VERSION 5.7 ;
  NOWIREEXTENSIONATPIN ON ;
  DIVIDERCHAR "/" ;
  BUSBITCHARS "[]" ;
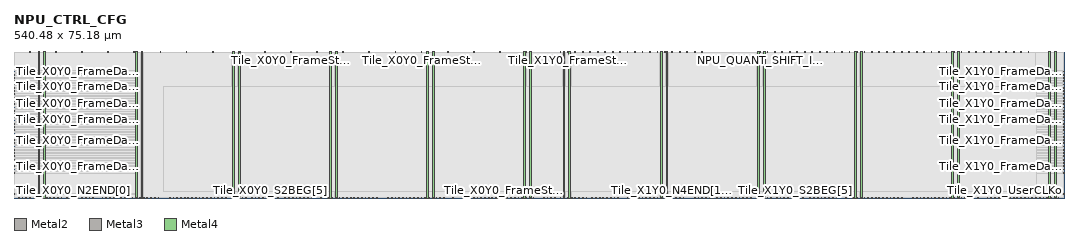
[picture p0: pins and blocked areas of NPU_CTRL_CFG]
MACRO NPU_CTRL_CFG
  CLASS BLOCK ;
  FOREIGN NPU_CTRL_CFG ;
  ORIGIN 0.000 0.000 ;
  SIZE 540.480 BY 75.180 ;
  PIN NPU_ARRAY_EN
    DIRECTION OUTPUT ;
    USE SIGNAL ;
    ANTENNADIFFAREA 2.647800 ;
    PORT
      LAYER Metal2 ;
        RECT 502.840 74.780 503.240 75.180 ;
    END
  END NPU_ARRAY_EN
  PIN NPU_COMPUTE_BANK_SWAP
    DIRECTION OUTPUT ;
    USE SIGNAL ;
    ANTENNADIFFAREA 2.647800 ;
    PORT
      LAYER Metal2 ;
        RECT 522.040 74.780 522.440 75.180 ;
    END
  END NPU_COMPUTE_BANK_SWAP
  PIN NPU_PSUM_LUT_EN
    DIRECTION OUTPUT ;
    USE SIGNAL ;
    ANTENNADIFFAREA 2.647800 ;
    PORT
      LAYER Metal2 ;
        RECT 510.520 74.780 510.920 75.180 ;
    END
  END NPU_PSUM_LUT_EN
  PIN NPU_PSUM_SKEW_EN
    DIRECTION OUTPUT ;
    USE SIGNAL ;
    ANTENNADIFFAREA 2.647800 ;
    PORT
      LAYER Metal2 ;
        RECT 518.200 74.780 518.600 75.180 ;
    END
  END NPU_PSUM_SKEW_EN
  PIN NPU_PSUM_SYSTOLIC_EN
    DIRECTION OUTPUT ;
    USE SIGNAL ;
    ANTENNADIFFAREA 2.647800 ;
    PORT
      LAYER Metal2 ;
        RECT 506.680 74.780 507.080 75.180 ;
    END
  END NPU_PSUM_SYSTOLIC_EN
  PIN NPU_QUANT_SHIFT_EN
    DIRECTION OUTPUT ;
    USE SIGNAL ;
    ANTENNADIFFAREA 2.647800 ;
    PORT
      LAYER Metal2 ;
        RECT 499.000 74.780 499.400 75.180 ;
    END
  END NPU_QUANT_SHIFT_EN
  PIN NPU_QUANT_SHIFT_IN0
    DIRECTION OUTPUT ;
    USE SIGNAL ;
    ANTENNADIFFAREA 2.647800 ;
    PORT
      LAYER Metal2 ;
        RECT 383.800 74.780 384.200 75.180 ;
    END
  END NPU_QUANT_SHIFT_IN0
  PIN NPU_QUANT_SHIFT_IN1
    DIRECTION OUTPUT ;
    USE SIGNAL ;
    ANTENNADIFFAREA 2.647800 ;
    PORT
      LAYER Metal2 ;
        RECT 387.640 74.780 388.040 75.180 ;
    END
  END NPU_QUANT_SHIFT_IN1
  PIN NPU_QUANT_SHIFT_IN10
    DIRECTION OUTPUT ;
    USE SIGNAL ;
    ANTENNADIFFAREA 2.647800 ;
    PORT
      LAYER Metal2 ;
        RECT 422.200 74.780 422.600 75.180 ;
    END
  END NPU_QUANT_SHIFT_IN10
  PIN NPU_QUANT_SHIFT_IN11
    DIRECTION OUTPUT ;
    USE SIGNAL ;
    ANTENNADIFFAREA 2.647800 ;
    PORT
      LAYER Metal2 ;
        RECT 426.040 74.780 426.440 75.180 ;
    END
  END NPU_QUANT_SHIFT_IN11
  PIN NPU_QUANT_SHIFT_IN12
    DIRECTION OUTPUT ;
    USE SIGNAL ;
    ANTENNADIFFAREA 2.647800 ;
    PORT
      LAYER Metal2 ;
        RECT 429.880 74.780 430.280 75.180 ;
    END
  END NPU_QUANT_SHIFT_IN12
  PIN NPU_QUANT_SHIFT_IN13
    DIRECTION OUTPUT ;
    USE SIGNAL ;
    ANTENNADIFFAREA 2.647800 ;
    PORT
      LAYER Metal2 ;
        RECT 433.720 74.780 434.120 75.180 ;
    END
  END NPU_QUANT_SHIFT_IN13
  PIN NPU_QUANT_SHIFT_IN14
    DIRECTION OUTPUT ;
    USE SIGNAL ;
    ANTENNADIFFAREA 2.647800 ;
    PORT
      LAYER Metal2 ;
        RECT 437.560 74.780 437.960 75.180 ;
    END
  END NPU_QUANT_SHIFT_IN14
  PIN NPU_QUANT_SHIFT_IN15
    DIRECTION OUTPUT ;
    USE SIGNAL ;
    ANTENNADIFFAREA 2.647800 ;
    PORT
      LAYER Metal2 ;
        RECT 441.400 74.780 441.800 75.180 ;
    END
  END NPU_QUANT_SHIFT_IN15
  PIN NPU_QUANT_SHIFT_IN16
    DIRECTION OUTPUT ;
    USE SIGNAL ;
    ANTENNADIFFAREA 2.647800 ;
    PORT
      LAYER Metal2 ;
        RECT 445.240 74.780 445.640 75.180 ;
    END
  END NPU_QUANT_SHIFT_IN16
  PIN NPU_QUANT_SHIFT_IN17
    DIRECTION OUTPUT ;
    USE SIGNAL ;
    ANTENNADIFFAREA 2.647800 ;
    PORT
      LAYER Metal2 ;
        RECT 449.080 74.780 449.480 75.180 ;
    END
  END NPU_QUANT_SHIFT_IN17
  PIN NPU_QUANT_SHIFT_IN18
    DIRECTION OUTPUT ;
    USE SIGNAL ;
    ANTENNADIFFAREA 2.647800 ;
    PORT
      LAYER Metal2 ;
        RECT 452.920 74.780 453.320 75.180 ;
    END
  END NPU_QUANT_SHIFT_IN18
  PIN NPU_QUANT_SHIFT_IN19
    DIRECTION OUTPUT ;
    USE SIGNAL ;
    ANTENNADIFFAREA 2.647800 ;
    PORT
      LAYER Metal2 ;
        RECT 456.760 74.780 457.160 75.180 ;
    END
  END NPU_QUANT_SHIFT_IN19
  PIN NPU_QUANT_SHIFT_IN2
    DIRECTION OUTPUT ;
    USE SIGNAL ;
    ANTENNADIFFAREA 2.647800 ;
    PORT
      LAYER Metal2 ;
        RECT 391.480 74.780 391.880 75.180 ;
    END
  END NPU_QUANT_SHIFT_IN2
  PIN NPU_QUANT_SHIFT_IN20
    DIRECTION OUTPUT ;
    USE SIGNAL ;
    ANTENNADIFFAREA 2.647800 ;
    PORT
      LAYER Metal2 ;
        RECT 460.600 74.780 461.000 75.180 ;
    END
  END NPU_QUANT_SHIFT_IN20
  PIN NPU_QUANT_SHIFT_IN21
    DIRECTION OUTPUT ;
    USE SIGNAL ;
    ANTENNADIFFAREA 2.647800 ;
    PORT
      LAYER Metal2 ;
        RECT 464.440 74.780 464.840 75.180 ;
    END
  END NPU_QUANT_SHIFT_IN21
  PIN NPU_QUANT_SHIFT_IN22
    DIRECTION OUTPUT ;
    USE SIGNAL ;
    ANTENNADIFFAREA 2.647800 ;
    PORT
      LAYER Metal2 ;
        RECT 468.280 74.780 468.680 75.180 ;
    END
  END NPU_QUANT_SHIFT_IN22
  PIN NPU_QUANT_SHIFT_IN23
    DIRECTION OUTPUT ;
    USE SIGNAL ;
    ANTENNADIFFAREA 2.647800 ;
    PORT
      LAYER Metal2 ;
        RECT 472.120 74.780 472.520 75.180 ;
    END
  END NPU_QUANT_SHIFT_IN23
  PIN NPU_QUANT_SHIFT_IN24
    DIRECTION OUTPUT ;
    USE SIGNAL ;
    ANTENNADIFFAREA 2.647800 ;
    PORT
      LAYER Metal2 ;
        RECT 475.960 74.780 476.360 75.180 ;
    END
  END NPU_QUANT_SHIFT_IN24
  PIN NPU_QUANT_SHIFT_IN25
    DIRECTION OUTPUT ;
    USE SIGNAL ;
    ANTENNADIFFAREA 2.647800 ;
    PORT
      LAYER Metal2 ;
        RECT 479.800 74.780 480.200 75.180 ;
    END
  END NPU_QUANT_SHIFT_IN25
  PIN NPU_QUANT_SHIFT_IN26
    DIRECTION OUTPUT ;
    USE SIGNAL ;
    ANTENNADIFFAREA 2.647800 ;
    PORT
      LAYER Metal2 ;
        RECT 483.640 74.780 484.040 75.180 ;
    END
  END NPU_QUANT_SHIFT_IN26
  PIN NPU_QUANT_SHIFT_IN27
    DIRECTION OUTPUT ;
    USE SIGNAL ;
    ANTENNADIFFAREA 2.647800 ;
    PORT
      LAYER Metal2 ;
        RECT 487.480 74.780 487.880 75.180 ;
    END
  END NPU_QUANT_SHIFT_IN27
  PIN NPU_QUANT_SHIFT_IN28
    DIRECTION OUTPUT ;
    USE SIGNAL ;
    ANTENNADIFFAREA 2.647800 ;
    PORT
      LAYER Metal2 ;
        RECT 491.320 74.780 491.720 75.180 ;
    END
  END NPU_QUANT_SHIFT_IN28
  PIN NPU_QUANT_SHIFT_IN29
    DIRECTION OUTPUT ;
    USE SIGNAL ;
    ANTENNADIFFAREA 2.647800 ;
    PORT
      LAYER Metal2 ;
        RECT 495.160 74.780 495.560 75.180 ;
    END
  END NPU_QUANT_SHIFT_IN29
  PIN NPU_QUANT_SHIFT_IN3
    DIRECTION OUTPUT ;
    USE SIGNAL ;
    ANTENNADIFFAREA 2.647800 ;
    PORT
      LAYER Metal2 ;
        RECT 395.320 74.780 395.720 75.180 ;
    END
  END NPU_QUANT_SHIFT_IN3
  PIN NPU_QUANT_SHIFT_IN4
    DIRECTION OUTPUT ;
    USE SIGNAL ;
    ANTENNADIFFAREA 2.647800 ;
    PORT
      LAYER Metal2 ;
        RECT 399.160 74.780 399.560 75.180 ;
    END
  END NPU_QUANT_SHIFT_IN4
  PIN NPU_QUANT_SHIFT_IN5
    DIRECTION OUTPUT ;
    USE SIGNAL ;
    ANTENNADIFFAREA 2.647800 ;
    PORT
      LAYER Metal2 ;
        RECT 403.000 74.780 403.400 75.180 ;
    END
  END NPU_QUANT_SHIFT_IN5
  PIN NPU_QUANT_SHIFT_IN6
    DIRECTION OUTPUT ;
    USE SIGNAL ;
    ANTENNADIFFAREA 2.647800 ;
    PORT
      LAYER Metal2 ;
        RECT 406.840 74.780 407.240 75.180 ;
    END
  END NPU_QUANT_SHIFT_IN6
  PIN NPU_QUANT_SHIFT_IN7
    DIRECTION OUTPUT ;
    USE SIGNAL ;
    ANTENNADIFFAREA 2.647800 ;
    PORT
      LAYER Metal2 ;
        RECT 410.680 74.780 411.080 75.180 ;
    END
  END NPU_QUANT_SHIFT_IN7
  PIN NPU_QUANT_SHIFT_IN8
    DIRECTION OUTPUT ;
    USE SIGNAL ;
    ANTENNADIFFAREA 2.647800 ;
    PORT
      LAYER Metal2 ;
        RECT 414.520 74.780 414.920 75.180 ;
    END
  END NPU_QUANT_SHIFT_IN8
  PIN NPU_QUANT_SHIFT_IN9
    DIRECTION OUTPUT ;
    USE SIGNAL ;
    ANTENNADIFFAREA 2.647800 ;
    PORT
      LAYER Metal2 ;
        RECT 418.360 74.780 418.760 75.180 ;
    END
  END NPU_QUANT_SHIFT_IN9
  PIN NPU_SWAP_WEIGHTS
    DIRECTION OUTPUT ;
    USE SIGNAL ;
    ANTENNADIFFAREA 2.647800 ;
    PORT
      LAYER Metal2 ;
        RECT 514.360 74.780 514.760 75.180 ;
    END
  END NPU_SWAP_WEIGHTS
  PIN Tile_X0Y0_Ci
    DIRECTION INPUT ;
    USE SIGNAL ;
    PORT
      LAYER Metal2 ;
        RECT 225.880 0.000 226.280 0.400 ;
    END
  END Tile_X0Y0_Ci
  PIN Tile_X0Y0_FrameData[0]
    DIRECTION INPUT ;
    USE SIGNAL ;
    ANTENNAGATEAREA 0.542100 ;
    ANTENNADIFFAREA 18.138599 ;
    PORT
      LAYER Metal3 ;
        RECT 0.000 12.820 0.400 13.220 ;
    END
  END Tile_X0Y0_FrameData[0]
  PIN Tile_X0Y0_FrameData[10]
    DIRECTION INPUT ;
    USE SIGNAL ;
    ANTENNAGATEAREA 0.542100 ;
    ANTENNADIFFAREA 12.092400 ;
    PORT
      LAYER Metal3 ;
        RECT 0.000 29.620 0.400 30.020 ;
    END
  END Tile_X0Y0_FrameData[10]
  PIN Tile_X0Y0_FrameData[11]
    DIRECTION INPUT ;
    USE SIGNAL ;
    ANTENNAGATEAREA 0.542100 ;
    ANTENNADIFFAREA 18.138599 ;
    PORT
      LAYER Metal3 ;
        RECT 0.000 31.300 0.400 31.700 ;
    END
  END Tile_X0Y0_FrameData[11]
  PIN Tile_X0Y0_FrameData[12]
    DIRECTION INPUT ;
    USE SIGNAL ;
    ANTENNAGATEAREA 0.542100 ;
    ANTENNADIFFAREA 18.138599 ;
    PORT
      LAYER Metal3 ;
        RECT 0.000 32.980 0.400 33.380 ;
    END
  END Tile_X0Y0_FrameData[12]
  PIN Tile_X0Y0_FrameData[13]
    DIRECTION INPUT ;
    USE SIGNAL ;
    ANTENNAGATEAREA 0.542100 ;
    ANTENNADIFFAREA 18.138599 ;
    PORT
      LAYER Metal3 ;
        RECT 0.000 34.660 0.400 35.060 ;
    END
  END Tile_X0Y0_FrameData[13]
  PIN Tile_X0Y0_FrameData[14]
    DIRECTION INPUT ;
    USE SIGNAL ;
    ANTENNAGATEAREA 0.542100 ;
    ANTENNADIFFAREA 18.138599 ;
    PORT
      LAYER Metal3 ;
        RECT 0.000 36.340 0.400 36.740 ;
    END
  END Tile_X0Y0_FrameData[14]
  PIN Tile_X0Y0_FrameData[15]
    DIRECTION INPUT ;
    USE SIGNAL ;
    ANTENNAGATEAREA 0.542100 ;
    ANTENNADIFFAREA 18.138599 ;
    PORT
      LAYER Metal3 ;
        RECT 0.000 38.020 0.400 38.420 ;
    END
  END Tile_X0Y0_FrameData[15]
  PIN Tile_X0Y0_FrameData[16]
    DIRECTION INPUT ;
    USE SIGNAL ;
    ANTENNAGATEAREA 0.542100 ;
    ANTENNADIFFAREA 18.138599 ;
    PORT
      LAYER Metal3 ;
        RECT 0.000 39.700 0.400 40.100 ;
    END
  END Tile_X0Y0_FrameData[16]
  PIN Tile_X0Y0_FrameData[17]
    DIRECTION INPUT ;
    USE SIGNAL ;
    ANTENNAGATEAREA 0.542100 ;
    ANTENNADIFFAREA 18.138599 ;
    PORT
      LAYER Metal3 ;
        RECT 0.000 41.380 0.400 41.780 ;
    END
  END Tile_X0Y0_FrameData[17]
  PIN Tile_X0Y0_FrameData[18]
    DIRECTION INPUT ;
    USE SIGNAL ;
    ANTENNAGATEAREA 0.542100 ;
    PORT
      LAYER Metal3 ;
        RECT 0.000 43.060 0.400 43.460 ;
    END
  END Tile_X0Y0_FrameData[18]
  PIN Tile_X0Y0_FrameData[19]
    DIRECTION INPUT ;
    USE SIGNAL ;
    ANTENNAGATEAREA 0.542100 ;
    PORT
      LAYER Metal3 ;
        RECT 0.000 44.740 0.400 45.140 ;
    END
  END Tile_X0Y0_FrameData[19]
  PIN Tile_X0Y0_FrameData[1]
    DIRECTION INPUT ;
    USE SIGNAL ;
    ANTENNAGATEAREA 0.542100 ;
    ANTENNADIFFAREA 18.138599 ;
    PORT
      LAYER Metal3 ;
        RECT 0.000 14.500 0.400 14.900 ;
    END
  END Tile_X0Y0_FrameData[1]
  PIN Tile_X0Y0_FrameData[20]
    DIRECTION INPUT ;
    USE SIGNAL ;
    ANTENNAGATEAREA 0.542100 ;
    PORT
      LAYER Metal3 ;
        RECT 0.000 46.420 0.400 46.820 ;
    END
  END Tile_X0Y0_FrameData[20]
  PIN Tile_X0Y0_FrameData[21]
    DIRECTION INPUT ;
    USE SIGNAL ;
    ANTENNAGATEAREA 0.542100 ;
    PORT
      LAYER Metal3 ;
        RECT 0.000 48.100 0.400 48.500 ;
    END
  END Tile_X0Y0_FrameData[21]
  PIN Tile_X0Y0_FrameData[22]
    DIRECTION INPUT ;
    USE SIGNAL ;
    ANTENNAGATEAREA 0.542100 ;
    PORT
      LAYER Metal3 ;
        RECT 0.000 49.780 0.400 50.180 ;
    END
  END Tile_X0Y0_FrameData[22]
  PIN Tile_X0Y0_FrameData[23]
    DIRECTION INPUT ;
    USE SIGNAL ;
    ANTENNAGATEAREA 0.542100 ;
    PORT
      LAYER Metal3 ;
        RECT 0.000 51.460 0.400 51.860 ;
    END
  END Tile_X0Y0_FrameData[23]
  PIN Tile_X0Y0_FrameData[24]
    DIRECTION INPUT ;
    USE SIGNAL ;
    ANTENNAGATEAREA 0.542100 ;
    PORT
      LAYER Metal3 ;
        RECT 0.000 53.140 0.400 53.540 ;
    END
  END Tile_X0Y0_FrameData[24]
  PIN Tile_X0Y0_FrameData[25]
    DIRECTION INPUT ;
    USE SIGNAL ;
    ANTENNAGATEAREA 0.722800 ;
    ANTENNADIFFAREA 32.246399 ;
    PORT
      LAYER Metal3 ;
        RECT 0.000 54.820 0.400 55.220 ;
    END
  END Tile_X0Y0_FrameData[25]
  PIN Tile_X0Y0_FrameData[26]
    DIRECTION INPUT ;
    USE SIGNAL ;
    ANTENNAGATEAREA 0.722800 ;
    PORT
      LAYER Metal3 ;
        RECT 0.000 56.500 0.400 56.900 ;
    END
  END Tile_X0Y0_FrameData[26]
  PIN Tile_X0Y0_FrameData[27]
    DIRECTION INPUT ;
    USE SIGNAL ;
    ANTENNAGATEAREA 0.722800 ;
    PORT
      LAYER Metal3 ;
        RECT 0.000 58.180 0.400 58.580 ;
    END
  END Tile_X0Y0_FrameData[27]
  PIN Tile_X0Y0_FrameData[28]
    DIRECTION INPUT ;
    USE SIGNAL ;
    ANTENNAGATEAREA 0.903500 ;
    ANTENNADIFFAREA 24.184799 ;
    PORT
      LAYER Metal3 ;
        RECT 0.000 59.860 0.400 60.260 ;
    END
  END Tile_X0Y0_FrameData[28]
  PIN Tile_X0Y0_FrameData[29]
    DIRECTION INPUT ;
    USE SIGNAL ;
    ANTENNAGATEAREA 0.903500 ;
    ANTENNADIFFAREA 30.230999 ;
    PORT
      LAYER Metal3 ;
        RECT 0.000 61.540 0.400 61.940 ;
    END
  END Tile_X0Y0_FrameData[29]
  PIN Tile_X0Y0_FrameData[2]
    DIRECTION INPUT ;
    USE SIGNAL ;
    ANTENNAGATEAREA 0.542100 ;
    ANTENNADIFFAREA 18.138599 ;
    PORT
      LAYER Metal3 ;
        RECT 0.000 16.180 0.400 16.580 ;
    END
  END Tile_X0Y0_FrameData[2]
  PIN Tile_X0Y0_FrameData[30]
    DIRECTION INPUT ;
    USE SIGNAL ;
    ANTENNAGATEAREA 0.903500 ;
    ANTENNADIFFAREA 12.092400 ;
    PORT
      LAYER Metal3 ;
        RECT 0.000 63.220 0.400 63.620 ;
    END
  END Tile_X0Y0_FrameData[30]
  PIN Tile_X0Y0_FrameData[31]
    DIRECTION INPUT ;
    USE SIGNAL ;
    ANTENNAGATEAREA 0.903500 ;
    ANTENNADIFFAREA 50.384998 ;
    PORT
      LAYER Metal3 ;
        RECT 0.000 64.900 0.400 65.300 ;
    END
  END Tile_X0Y0_FrameData[31]
  PIN Tile_X0Y0_FrameData[3]
    DIRECTION INPUT ;
    USE SIGNAL ;
    ANTENNAGATEAREA 0.542100 ;
    ANTENNADIFFAREA 18.138599 ;
    PORT
      LAYER Metal3 ;
        RECT 0.000 17.860 0.400 18.260 ;
    END
  END Tile_X0Y0_FrameData[3]
  PIN Tile_X0Y0_FrameData[4]
    DIRECTION INPUT ;
    USE SIGNAL ;
    ANTENNAGATEAREA 0.542100 ;
    ANTENNADIFFAREA 18.138599 ;
    PORT
      LAYER Metal3 ;
        RECT 0.000 19.540 0.400 19.940 ;
    END
  END Tile_X0Y0_FrameData[4]
  PIN Tile_X0Y0_FrameData[5]
    DIRECTION INPUT ;
    USE SIGNAL ;
    ANTENNAGATEAREA 0.542100 ;
    ANTENNADIFFAREA 18.138599 ;
    PORT
      LAYER Metal3 ;
        RECT 0.000 21.220 0.400 21.620 ;
    END
  END Tile_X0Y0_FrameData[5]
  PIN Tile_X0Y0_FrameData[6]
    DIRECTION INPUT ;
    USE SIGNAL ;
    ANTENNAGATEAREA 0.542100 ;
    ANTENNADIFFAREA 18.138599 ;
    PORT
      LAYER Metal3 ;
        RECT 0.000 22.900 0.400 23.300 ;
    END
  END Tile_X0Y0_FrameData[6]
  PIN Tile_X0Y0_FrameData[7]
    DIRECTION INPUT ;
    USE SIGNAL ;
    ANTENNAGATEAREA 0.542100 ;
    ANTENNADIFFAREA 18.138599 ;
    PORT
      LAYER Metal3 ;
        RECT 0.000 24.580 0.400 24.980 ;
    END
  END Tile_X0Y0_FrameData[7]
  PIN Tile_X0Y0_FrameData[8]
    DIRECTION INPUT ;
    USE SIGNAL ;
    ANTENNAGATEAREA 0.542100 ;
    ANTENNADIFFAREA 18.138599 ;
    PORT
      LAYER Metal3 ;
        RECT 0.000 26.260 0.400 26.660 ;
    END
  END Tile_X0Y0_FrameData[8]
  PIN Tile_X0Y0_FrameData[9]
    DIRECTION INPUT ;
    USE SIGNAL ;
    ANTENNAGATEAREA 0.542100 ;
    ANTENNADIFFAREA 18.138599 ;
    PORT
      LAYER Metal3 ;
        RECT 0.000 27.940 0.400 28.340 ;
    END
  END Tile_X0Y0_FrameData[9]
  PIN Tile_X0Y0_FrameStrobe[0]
    DIRECTION INPUT ;
    USE SIGNAL ;
    ANTENNAGATEAREA 11.745500 ;
    PORT
      LAYER Metal2 ;
        RECT 230.680 0.000 231.080 0.400 ;
    END
  END Tile_X0Y0_FrameStrobe[0]
  PIN Tile_X0Y0_FrameStrobe[10]
    DIRECTION INPUT ;
    USE SIGNAL ;
    ANTENNAGATEAREA 0.180700 ;
    PORT
      LAYER Metal2 ;
        RECT 249.880 0.000 250.280 0.400 ;
    END
  END Tile_X0Y0_FrameStrobe[10]
  PIN Tile_X0Y0_FrameStrobe[11]
    DIRECTION INPUT ;
    USE SIGNAL ;
    ANTENNAGATEAREA 0.180700 ;
    PORT
      LAYER Metal2 ;
        RECT 251.800 0.000 252.200 0.400 ;
    END
  END Tile_X0Y0_FrameStrobe[11]
  PIN Tile_X0Y0_FrameStrobe[12]
    DIRECTION INPUT ;
    USE SIGNAL ;
    ANTENNAGATEAREA 0.180700 ;
    PORT
      LAYER Metal2 ;
        RECT 253.720 0.000 254.120 0.400 ;
    END
  END Tile_X0Y0_FrameStrobe[12]
  PIN Tile_X0Y0_FrameStrobe[13]
    DIRECTION INPUT ;
    USE SIGNAL ;
    ANTENNAGATEAREA 0.180700 ;
    PORT
      LAYER Metal2 ;
        RECT 255.640 0.000 256.040 0.400 ;
    END
  END Tile_X0Y0_FrameStrobe[13]
  PIN Tile_X0Y0_FrameStrobe[14]
    DIRECTION INPUT ;
    USE SIGNAL ;
    ANTENNAGATEAREA 0.180700 ;
    PORT
      LAYER Metal2 ;
        RECT 257.560 0.000 257.960 0.400 ;
    END
  END Tile_X0Y0_FrameStrobe[14]
  PIN Tile_X0Y0_FrameStrobe[15]
    DIRECTION INPUT ;
    USE SIGNAL ;
    ANTENNAGATEAREA 0.180700 ;
    PORT
      LAYER Metal2 ;
        RECT 259.480 0.000 259.880 0.400 ;
    END
  END Tile_X0Y0_FrameStrobe[15]
  PIN Tile_X0Y0_FrameStrobe[16]
    DIRECTION INPUT ;
    USE SIGNAL ;
    ANTENNAGATEAREA 0.180700 ;
    PORT
      LAYER Metal2 ;
        RECT 261.400 0.000 261.800 0.400 ;
    END
  END Tile_X0Y0_FrameStrobe[16]
  PIN Tile_X0Y0_FrameStrobe[17]
    DIRECTION INPUT ;
    USE SIGNAL ;
    ANTENNAGATEAREA 0.180700 ;
    PORT
      LAYER Metal2 ;
        RECT 263.320 0.000 263.720 0.400 ;
    END
  END Tile_X0Y0_FrameStrobe[17]
  PIN Tile_X0Y0_FrameStrobe[18]
    DIRECTION INPUT ;
    USE SIGNAL ;
    ANTENNAGATEAREA 0.180700 ;
    PORT
      LAYER Metal2 ;
        RECT 265.240 0.000 265.640 0.400 ;
    END
  END Tile_X0Y0_FrameStrobe[18]
  PIN Tile_X0Y0_FrameStrobe[19]
    DIRECTION INPUT ;
    USE SIGNAL ;
    ANTENNAGATEAREA 0.180700 ;
    PORT
      LAYER Metal2 ;
        RECT 267.160 0.000 267.560 0.400 ;
    END
  END Tile_X0Y0_FrameStrobe[19]
  PIN Tile_X0Y0_FrameStrobe[1]
    DIRECTION INPUT ;
    USE SIGNAL ;
    ANTENNAGATEAREA 1.626300 ;
    PORT
      LAYER Metal2 ;
        RECT 232.600 0.000 233.000 0.400 ;
    END
  END Tile_X0Y0_FrameStrobe[1]
  PIN Tile_X0Y0_FrameStrobe[2]
    DIRECTION INPUT ;
    USE SIGNAL ;
    ANTENNAGATEAREA 0.180700 ;
    PORT
      LAYER Metal2 ;
        RECT 234.520 0.000 234.920 0.400 ;
    END
  END Tile_X0Y0_FrameStrobe[2]
  PIN Tile_X0Y0_FrameStrobe[3]
    DIRECTION INPUT ;
    USE SIGNAL ;
    ANTENNAGATEAREA 0.180700 ;
    PORT
      LAYER Metal2 ;
        RECT 236.440 0.000 236.840 0.400 ;
    END
  END Tile_X0Y0_FrameStrobe[3]
  PIN Tile_X0Y0_FrameStrobe[4]
    DIRECTION INPUT ;
    USE SIGNAL ;
    ANTENNAGATEAREA 0.180700 ;
    PORT
      LAYER Metal2 ;
        RECT 238.360 0.000 238.760 0.400 ;
    END
  END Tile_X0Y0_FrameStrobe[4]
  PIN Tile_X0Y0_FrameStrobe[5]
    DIRECTION INPUT ;
    USE SIGNAL ;
    ANTENNAGATEAREA 0.180700 ;
    PORT
      LAYER Metal2 ;
        RECT 240.280 0.000 240.680 0.400 ;
    END
  END Tile_X0Y0_FrameStrobe[5]
  PIN Tile_X0Y0_FrameStrobe[6]
    DIRECTION INPUT ;
    USE SIGNAL ;
    ANTENNAGATEAREA 0.180700 ;
    PORT
      LAYER Metal2 ;
        RECT 242.200 0.000 242.600 0.400 ;
    END
  END Tile_X0Y0_FrameStrobe[6]
  PIN Tile_X0Y0_FrameStrobe[7]
    DIRECTION INPUT ;
    USE SIGNAL ;
    ANTENNAGATEAREA 0.180700 ;
    PORT
      LAYER Metal2 ;
        RECT 244.120 0.000 244.520 0.400 ;
    END
  END Tile_X0Y0_FrameStrobe[7]
  PIN Tile_X0Y0_FrameStrobe[8]
    DIRECTION INPUT ;
    USE SIGNAL ;
    ANTENNAGATEAREA 0.180700 ;
    PORT
      LAYER Metal2 ;
        RECT 246.040 0.000 246.440 0.400 ;
    END
  END Tile_X0Y0_FrameStrobe[8]
  PIN Tile_X0Y0_FrameStrobe[9]
    DIRECTION INPUT ;
    USE SIGNAL ;
    ANTENNAGATEAREA 0.180700 ;
    PORT
      LAYER Metal2 ;
        RECT 247.960 0.000 248.360 0.400 ;
    END
  END Tile_X0Y0_FrameStrobe[9]
  PIN Tile_X0Y0_FrameStrobe_O[0]
    DIRECTION OUTPUT ;
    USE SIGNAL ;
    ANTENNADIFFAREA 2.724000 ;
    PORT
      LAYER Metal2 ;
        RECT 7.960 74.780 8.360 75.180 ;
    END
  END Tile_X0Y0_FrameStrobe_O[0]
  PIN Tile_X0Y0_FrameStrobe_O[10]
    DIRECTION OUTPUT ;
    USE SIGNAL ;
    ANTENNADIFFAREA 2.724000 ;
    PORT
      LAYER Metal2 ;
        RECT 142.360 74.780 142.760 75.180 ;
    END
  END Tile_X0Y0_FrameStrobe_O[10]
  PIN Tile_X0Y0_FrameStrobe_O[11]
    DIRECTION OUTPUT ;
    USE SIGNAL ;
    ANTENNADIFFAREA 2.724000 ;
    PORT
      LAYER Metal2 ;
        RECT 155.800 74.780 156.200 75.180 ;
    END
  END Tile_X0Y0_FrameStrobe_O[11]
  PIN Tile_X0Y0_FrameStrobe_O[12]
    DIRECTION OUTPUT ;
    USE SIGNAL ;
    ANTENNADIFFAREA 2.724000 ;
    PORT
      LAYER Metal2 ;
        RECT 169.240 74.780 169.640 75.180 ;
    END
  END Tile_X0Y0_FrameStrobe_O[12]
  PIN Tile_X0Y0_FrameStrobe_O[13]
    DIRECTION OUTPUT ;
    USE SIGNAL ;
    ANTENNADIFFAREA 2.724000 ;
    PORT
      LAYER Metal2 ;
        RECT 182.680 74.780 183.080 75.180 ;
    END
  END Tile_X0Y0_FrameStrobe_O[13]
  PIN Tile_X0Y0_FrameStrobe_O[14]
    DIRECTION OUTPUT ;
    USE SIGNAL ;
    ANTENNADIFFAREA 2.724000 ;
    PORT
      LAYER Metal2 ;
        RECT 196.120 74.780 196.520 75.180 ;
    END
  END Tile_X0Y0_FrameStrobe_O[14]
  PIN Tile_X0Y0_FrameStrobe_O[15]
    DIRECTION OUTPUT ;
    USE SIGNAL ;
    ANTENNADIFFAREA 2.724000 ;
    PORT
      LAYER Metal2 ;
        RECT 209.560 74.780 209.960 75.180 ;
    END
  END Tile_X0Y0_FrameStrobe_O[15]
  PIN Tile_X0Y0_FrameStrobe_O[16]
    DIRECTION OUTPUT ;
    USE SIGNAL ;
    ANTENNADIFFAREA 2.724000 ;
    PORT
      LAYER Metal2 ;
        RECT 223.000 74.780 223.400 75.180 ;
    END
  END Tile_X0Y0_FrameStrobe_O[16]
  PIN Tile_X0Y0_FrameStrobe_O[17]
    DIRECTION OUTPUT ;
    USE SIGNAL ;
    ANTENNADIFFAREA 2.724000 ;
    PORT
      LAYER Metal2 ;
        RECT 236.440 74.780 236.840 75.180 ;
    END
  END Tile_X0Y0_FrameStrobe_O[17]
  PIN Tile_X0Y0_FrameStrobe_O[18]
    DIRECTION OUTPUT ;
    USE SIGNAL ;
    ANTENNADIFFAREA 2.724000 ;
    PORT
      LAYER Metal2 ;
        RECT 249.880 74.780 250.280 75.180 ;
    END
  END Tile_X0Y0_FrameStrobe_O[18]
  PIN Tile_X0Y0_FrameStrobe_O[19]
    DIRECTION OUTPUT ;
    USE SIGNAL ;
    ANTENNADIFFAREA 2.724000 ;
    PORT
      LAYER Metal2 ;
        RECT 263.320 74.780 263.720 75.180 ;
    END
  END Tile_X0Y0_FrameStrobe_O[19]
  PIN Tile_X0Y0_FrameStrobe_O[1]
    DIRECTION OUTPUT ;
    USE SIGNAL ;
    ANTENNADIFFAREA 2.724000 ;
    PORT
      LAYER Metal2 ;
        RECT 21.400 74.780 21.800 75.180 ;
    END
  END Tile_X0Y0_FrameStrobe_O[1]
  PIN Tile_X0Y0_FrameStrobe_O[2]
    DIRECTION OUTPUT ;
    USE SIGNAL ;
    ANTENNADIFFAREA 2.724000 ;
    PORT
      LAYER Metal2 ;
        RECT 34.840 74.780 35.240 75.180 ;
    END
  END Tile_X0Y0_FrameStrobe_O[2]
  PIN Tile_X0Y0_FrameStrobe_O[3]
    DIRECTION OUTPUT ;
    USE SIGNAL ;
    ANTENNADIFFAREA 2.724000 ;
    PORT
      LAYER Metal2 ;
        RECT 48.280 74.780 48.680 75.180 ;
    END
  END Tile_X0Y0_FrameStrobe_O[3]
  PIN Tile_X0Y0_FrameStrobe_O[4]
    DIRECTION OUTPUT ;
    USE SIGNAL ;
    ANTENNADIFFAREA 2.724000 ;
    PORT
      LAYER Metal2 ;
        RECT 61.720 74.780 62.120 75.180 ;
    END
  END Tile_X0Y0_FrameStrobe_O[4]
  PIN Tile_X0Y0_FrameStrobe_O[5]
    DIRECTION OUTPUT ;
    USE SIGNAL ;
    ANTENNADIFFAREA 2.724000 ;
    PORT
      LAYER Metal2 ;
        RECT 75.160 74.780 75.560 75.180 ;
    END
  END Tile_X0Y0_FrameStrobe_O[5]
  PIN Tile_X0Y0_FrameStrobe_O[6]
    DIRECTION OUTPUT ;
    USE SIGNAL ;
    ANTENNADIFFAREA 2.724000 ;
    PORT
      LAYER Metal2 ;
        RECT 88.600 74.780 89.000 75.180 ;
    END
  END Tile_X0Y0_FrameStrobe_O[6]
  PIN Tile_X0Y0_FrameStrobe_O[7]
    DIRECTION OUTPUT ;
    USE SIGNAL ;
    ANTENNADIFFAREA 2.724000 ;
    PORT
      LAYER Metal2 ;
        RECT 102.040 74.780 102.440 75.180 ;
    END
  END Tile_X0Y0_FrameStrobe_O[7]
  PIN Tile_X0Y0_FrameStrobe_O[8]
    DIRECTION OUTPUT ;
    USE SIGNAL ;
    ANTENNADIFFAREA 2.724000 ;
    PORT
      LAYER Metal2 ;
        RECT 115.480 74.780 115.880 75.180 ;
    END
  END Tile_X0Y0_FrameStrobe_O[8]
  PIN Tile_X0Y0_FrameStrobe_O[9]
    DIRECTION OUTPUT ;
    USE SIGNAL ;
    ANTENNADIFFAREA 2.724000 ;
    PORT
      LAYER Metal2 ;
        RECT 128.920 74.780 129.320 75.180 ;
    END
  END Tile_X0Y0_FrameStrobe_O[9]
  PIN Tile_X0Y0_N1END[0]
    DIRECTION INPUT ;
    USE SIGNAL ;
    ANTENNAGATEAREA 0.393900 ;
    PORT
      LAYER Metal2 ;
        RECT 2.200 0.000 2.600 0.400 ;
    END
  END Tile_X0Y0_N1END[0]
  PIN Tile_X0Y0_N1END[1]
    DIRECTION INPUT ;
    USE SIGNAL ;
    ANTENNAGATEAREA 0.393900 ;
    PORT
      LAYER Metal2 ;
        RECT 4.120 0.000 4.520 0.400 ;
    END
  END Tile_X0Y0_N1END[1]
  PIN Tile_X0Y0_N1END[2]
    DIRECTION INPUT ;
    USE SIGNAL ;
    ANTENNAGATEAREA 0.393900 ;
    PORT
      LAYER Metal2 ;
        RECT 6.040 0.000 6.440 0.400 ;
    END
  END Tile_X0Y0_N1END[2]
  PIN Tile_X0Y0_N1END[3]
    DIRECTION INPUT ;
    USE SIGNAL ;
    ANTENNAGATEAREA 0.180700 ;
    PORT
      LAYER Metal2 ;
        RECT 7.960 0.000 8.360 0.400 ;
    END
  END Tile_X0Y0_N1END[3]
  PIN Tile_X0Y0_N2END[0]
    DIRECTION INPUT ;
    USE SIGNAL ;
    ANTENNAGATEAREA 0.180700 ;
    PORT
      LAYER Metal2 ;
        RECT 27.160 0.000 27.560 0.400 ;
    END
  END Tile_X0Y0_N2END[0]
  PIN Tile_X0Y0_N2END[1]
    DIRECTION INPUT ;
    USE SIGNAL ;
    ANTENNAGATEAREA 0.180700 ;
    PORT
      LAYER Metal2 ;
        RECT 29.080 0.000 29.480 0.400 ;
    END
  END Tile_X0Y0_N2END[1]
  PIN Tile_X0Y0_N2END[2]
    DIRECTION INPUT ;
    USE SIGNAL ;
    ANTENNAGATEAREA 0.180700 ;
    PORT
      LAYER Metal2 ;
        RECT 31.000 0.000 31.400 0.400 ;
    END
  END Tile_X0Y0_N2END[2]
  PIN Tile_X0Y0_N2END[3]
    DIRECTION INPUT ;
    USE SIGNAL ;
    ANTENNAGATEAREA 0.180700 ;
    PORT
      LAYER Metal2 ;
        RECT 32.920 0.000 33.320 0.400 ;
    END
  END Tile_X0Y0_N2END[3]
  PIN Tile_X0Y0_N2END[4]
    DIRECTION INPUT ;
    USE SIGNAL ;
    ANTENNAGATEAREA 0.180700 ;
    PORT
      LAYER Metal2 ;
        RECT 34.840 0.000 35.240 0.400 ;
    END
  END Tile_X0Y0_N2END[4]
  PIN Tile_X0Y0_N2END[5]
    DIRECTION INPUT ;
    USE SIGNAL ;
    ANTENNAGATEAREA 0.393900 ;
    PORT
      LAYER Metal2 ;
        RECT 36.760 0.000 37.160 0.400 ;
    END
  END Tile_X0Y0_N2END[5]
  PIN Tile_X0Y0_N2END[6]
    DIRECTION INPUT ;
    USE SIGNAL ;
    ANTENNAGATEAREA 0.393900 ;
    PORT
      LAYER Metal2 ;
        RECT 38.680 0.000 39.080 0.400 ;
    END
  END Tile_X0Y0_N2END[6]
  PIN Tile_X0Y0_N2END[7]
    DIRECTION INPUT ;
    USE SIGNAL ;
    ANTENNAGATEAREA 0.393900 ;
    PORT
      LAYER Metal2 ;
        RECT 40.600 0.000 41.000 0.400 ;
    END
  END Tile_X0Y0_N2END[7]
  PIN Tile_X0Y0_N2MID[0]
    DIRECTION INPUT ;
    USE SIGNAL ;
    ANTENNAGATEAREA 0.393900 ;
    PORT
      LAYER Metal2 ;
        RECT 10.840 0.000 11.240 0.400 ;
    END
  END Tile_X0Y0_N2MID[0]
  PIN Tile_X0Y0_N2MID[1]
    DIRECTION INPUT ;
    USE SIGNAL ;
    ANTENNAGATEAREA 0.393900 ;
    PORT
      LAYER Metal2 ;
        RECT 12.760 0.000 13.160 0.400 ;
    END
  END Tile_X0Y0_N2MID[1]
  PIN Tile_X0Y0_N2MID[2]
    DIRECTION INPUT ;
    USE SIGNAL ;
    ANTENNAGATEAREA 0.393900 ;
    PORT
      LAYER Metal2 ;
        RECT 14.680 0.000 15.080 0.400 ;
    END
  END Tile_X0Y0_N2MID[2]
  PIN Tile_X0Y0_N2MID[3]
    DIRECTION INPUT ;
    USE SIGNAL ;
    ANTENNAGATEAREA 0.180700 ;
    PORT
      LAYER Metal2 ;
        RECT 16.600 0.000 17.000 0.400 ;
    END
  END Tile_X0Y0_N2MID[3]
  PIN Tile_X0Y0_N2MID[4]
    DIRECTION INPUT ;
    USE SIGNAL ;
    ANTENNAGATEAREA 0.180700 ;
    PORT
      LAYER Metal2 ;
        RECT 18.520 0.000 18.920 0.400 ;
    END
  END Tile_X0Y0_N2MID[4]
  PIN Tile_X0Y0_N2MID[5]
    DIRECTION INPUT ;
    USE SIGNAL ;
    ANTENNAGATEAREA 0.393900 ;
    PORT
      LAYER Metal2 ;
        RECT 20.440 0.000 20.840 0.400 ;
    END
  END Tile_X0Y0_N2MID[5]
  PIN Tile_X0Y0_N2MID[6]
    DIRECTION INPUT ;
    USE SIGNAL ;
    ANTENNAGATEAREA 0.393900 ;
    PORT
      LAYER Metal2 ;
        RECT 22.360 0.000 22.760 0.400 ;
    END
  END Tile_X0Y0_N2MID[6]
  PIN Tile_X0Y0_N2MID[7]
    DIRECTION INPUT ;
    USE SIGNAL ;
    ANTENNAGATEAREA 0.393900 ;
    PORT
      LAYER Metal2 ;
        RECT 24.280 0.000 24.680 0.400 ;
    END
  END Tile_X0Y0_N2MID[7]
  PIN Tile_X0Y0_N4END[0]
    DIRECTION INPUT ;
    USE SIGNAL ;
    ANTENNAGATEAREA 0.607100 ;
    PORT
      LAYER Metal2 ;
        RECT 45.400 0.000 45.800 0.400 ;
    END
  END Tile_X0Y0_N4END[0]
  PIN Tile_X0Y0_N4END[10]
    DIRECTION INPUT ;
    USE SIGNAL ;
    ANTENNAGATEAREA 0.607100 ;
    PORT
      LAYER Metal2 ;
        RECT 64.600 0.000 65.000 0.400 ;
    END
  END Tile_X0Y0_N4END[10]
  PIN Tile_X0Y0_N4END[11]
    DIRECTION INPUT ;
    USE SIGNAL ;
    ANTENNAGATEAREA 0.607100 ;
    PORT
      LAYER Metal2 ;
        RECT 66.520 0.000 66.920 0.400 ;
    END
  END Tile_X0Y0_N4END[11]
  PIN Tile_X0Y0_N4END[12]
    DIRECTION INPUT ;
    USE SIGNAL ;
    ANTENNAGATEAREA 0.393900 ;
    ANTENNADIFFAREA 8.061600 ;
    PORT
      LAYER Metal2 ;
        RECT 68.440 0.000 68.840 0.400 ;
    END
  END Tile_X0Y0_N4END[12]
  PIN Tile_X0Y0_N4END[13]
    DIRECTION INPUT ;
    USE SIGNAL ;
    ANTENNAGATEAREA 0.607100 ;
    PORT
      LAYER Metal2 ;
        RECT 70.360 0.000 70.760 0.400 ;
    END
  END Tile_X0Y0_N4END[13]
  PIN Tile_X0Y0_N4END[14]
    DIRECTION INPUT ;
    USE SIGNAL ;
    ANTENNAGATEAREA 0.607100 ;
    PORT
      LAYER Metal2 ;
        RECT 72.280 0.000 72.680 0.400 ;
    END
  END Tile_X0Y0_N4END[14]
  PIN Tile_X0Y0_N4END[15]
    DIRECTION INPUT ;
    USE SIGNAL ;
    ANTENNAGATEAREA 0.393900 ;
    PORT
      LAYER Metal2 ;
        RECT 74.200 0.000 74.600 0.400 ;
    END
  END Tile_X0Y0_N4END[15]
  PIN Tile_X0Y0_N4END[1]
    DIRECTION INPUT ;
    USE SIGNAL ;
    ANTENNAGATEAREA 0.607100 ;
    PORT
      LAYER Metal2 ;
        RECT 47.320 0.000 47.720 0.400 ;
    END
  END Tile_X0Y0_N4END[1]
  PIN Tile_X0Y0_N4END[2]
    DIRECTION INPUT ;
    USE SIGNAL ;
    ANTENNAGATEAREA 0.607100 ;
    PORT
      LAYER Metal2 ;
        RECT 49.240 0.000 49.640 0.400 ;
    END
  END Tile_X0Y0_N4END[2]
  PIN Tile_X0Y0_N4END[3]
    DIRECTION INPUT ;
    USE SIGNAL ;
    ANTENNAGATEAREA 0.607100 ;
    ANTENNADIFFAREA 18.138599 ;
    PORT
      LAYER Metal2 ;
        RECT 51.160 0.000 51.560 0.400 ;
    END
  END Tile_X0Y0_N4END[3]
  PIN Tile_X0Y0_N4END[4]
    DIRECTION INPUT ;
    USE SIGNAL ;
    ANTENNAGATEAREA 0.607100 ;
    ANTENNADIFFAREA 18.138599 ;
    PORT
      LAYER Metal2 ;
        RECT 53.080 0.000 53.480 0.400 ;
    END
  END Tile_X0Y0_N4END[4]
  PIN Tile_X0Y0_N4END[5]
    DIRECTION INPUT ;
    USE SIGNAL ;
    ANTENNAGATEAREA 0.607100 ;
    ANTENNADIFFAREA 18.138599 ;
    PORT
      LAYER Metal2 ;
        RECT 55.000 0.000 55.400 0.400 ;
    END
  END Tile_X0Y0_N4END[5]
  PIN Tile_X0Y0_N4END[6]
    DIRECTION INPUT ;
    USE SIGNAL ;
    ANTENNAGATEAREA 0.607100 ;
    PORT
      LAYER Metal2 ;
        RECT 56.920 0.000 57.320 0.400 ;
    END
  END Tile_X0Y0_N4END[6]
  PIN Tile_X0Y0_N4END[7]
    DIRECTION INPUT ;
    USE SIGNAL ;
    ANTENNAGATEAREA 0.607100 ;
    PORT
      LAYER Metal2 ;
        RECT 58.840 0.000 59.240 0.400 ;
    END
  END Tile_X0Y0_N4END[7]
  PIN Tile_X0Y0_N4END[8]
    DIRECTION INPUT ;
    USE SIGNAL ;
    ANTENNAGATEAREA 0.607100 ;
    PORT
      LAYER Metal2 ;
        RECT 60.760 0.000 61.160 0.400 ;
    END
  END Tile_X0Y0_N4END[8]
  PIN Tile_X0Y0_N4END[9]
    DIRECTION INPUT ;
    USE SIGNAL ;
    ANTENNAGATEAREA 0.607100 ;
    PORT
      LAYER Metal2 ;
        RECT 62.680 0.000 63.080 0.400 ;
    END
  END Tile_X0Y0_N4END[9]
  PIN Tile_X0Y0_NN4END[0]
    DIRECTION INPUT ;
    USE SIGNAL ;
    ANTENNAGATEAREA 0.607100 ;
    PORT
      LAYER Metal2 ;
        RECT 79.960 0.000 80.360 0.400 ;
    END
  END Tile_X0Y0_NN4END[0]
  PIN Tile_X0Y0_NN4END[10]
    DIRECTION INPUT ;
    USE SIGNAL ;
    ANTENNAGATEAREA 0.607100 ;
    PORT
      LAYER Metal2 ;
        RECT 99.160 0.000 99.560 0.400 ;
    END
  END Tile_X0Y0_NN4END[10]
  PIN Tile_X0Y0_NN4END[11]
    DIRECTION INPUT ;
    USE SIGNAL ;
    ANTENNAGATEAREA 0.607100 ;
    PORT
      LAYER Metal2 ;
        RECT 101.080 0.000 101.480 0.400 ;
    END
  END Tile_X0Y0_NN4END[11]
  PIN Tile_X0Y0_NN4END[12]
    DIRECTION INPUT ;
    USE SIGNAL ;
    ANTENNAGATEAREA 0.607100 ;
    PORT
      LAYER Metal2 ;
        RECT 103.000 0.000 103.400 0.400 ;
    END
  END Tile_X0Y0_NN4END[12]
  PIN Tile_X0Y0_NN4END[13]
    DIRECTION INPUT ;
    USE SIGNAL ;
    ANTENNAGATEAREA 0.393900 ;
    PORT
      LAYER Metal2 ;
        RECT 104.920 0.000 105.320 0.400 ;
    END
  END Tile_X0Y0_NN4END[13]
  PIN Tile_X0Y0_NN4END[14]
    DIRECTION INPUT ;
    USE SIGNAL ;
    ANTENNAGATEAREA 0.607100 ;
    PORT
      LAYER Metal2 ;
        RECT 106.840 0.000 107.240 0.400 ;
    END
  END Tile_X0Y0_NN4END[14]
  PIN Tile_X0Y0_NN4END[15]
    DIRECTION INPUT ;
    USE SIGNAL ;
    ANTENNAGATEAREA 0.393900 ;
    PORT
      LAYER Metal2 ;
        RECT 108.760 0.000 109.160 0.400 ;
    END
  END Tile_X0Y0_NN4END[15]
  PIN Tile_X0Y0_NN4END[1]
    DIRECTION INPUT ;
    USE SIGNAL ;
    ANTENNAGATEAREA 0.607100 ;
    ANTENNADIFFAREA 18.138599 ;
    PORT
      LAYER Metal2 ;
        RECT 81.880 0.000 82.280 0.400 ;
    END
  END Tile_X0Y0_NN4END[1]
  PIN Tile_X0Y0_NN4END[2]
    DIRECTION INPUT ;
    USE SIGNAL ;
    ANTENNAGATEAREA 0.607100 ;
    ANTENNADIFFAREA 18.138599 ;
    PORT
      LAYER Metal2 ;
        RECT 83.800 0.000 84.200 0.400 ;
    END
  END Tile_X0Y0_NN4END[2]
  PIN Tile_X0Y0_NN4END[3]
    DIRECTION INPUT ;
    USE SIGNAL ;
    ANTENNAGATEAREA 0.607100 ;
    PORT
      LAYER Metal2 ;
        RECT 85.720 0.000 86.120 0.400 ;
    END
  END Tile_X0Y0_NN4END[3]
  PIN Tile_X0Y0_NN4END[4]
    DIRECTION INPUT ;
    USE SIGNAL ;
    ANTENNAGATEAREA 0.607100 ;
    PORT
      LAYER Metal2 ;
        RECT 87.640 0.000 88.040 0.400 ;
    END
  END Tile_X0Y0_NN4END[4]
  PIN Tile_X0Y0_NN4END[5]
    DIRECTION INPUT ;
    USE SIGNAL ;
    ANTENNAGATEAREA 0.607100 ;
    PORT
      LAYER Metal2 ;
        RECT 89.560 0.000 89.960 0.400 ;
    END
  END Tile_X0Y0_NN4END[5]
  PIN Tile_X0Y0_NN4END[6]
    DIRECTION INPUT ;
    USE SIGNAL ;
    ANTENNAGATEAREA 0.607100 ;
    ANTENNADIFFAREA 18.138599 ;
    PORT
      LAYER Metal2 ;
        RECT 91.480 0.000 91.880 0.400 ;
    END
  END Tile_X0Y0_NN4END[6]
  PIN Tile_X0Y0_NN4END[7]
    DIRECTION INPUT ;
    USE SIGNAL ;
    ANTENNAGATEAREA 0.607100 ;
    PORT
      LAYER Metal2 ;
        RECT 93.400 0.000 93.800 0.400 ;
    END
  END Tile_X0Y0_NN4END[7]
  PIN Tile_X0Y0_NN4END[8]
    DIRECTION INPUT ;
    USE SIGNAL ;
    ANTENNAGATEAREA 0.607100 ;
    PORT
      LAYER Metal2 ;
        RECT 95.320 0.000 95.720 0.400 ;
    END
  END Tile_X0Y0_NN4END[8]
  PIN Tile_X0Y0_NN4END[9]
    DIRECTION INPUT ;
    USE SIGNAL ;
    ANTENNAGATEAREA 0.607100 ;
    PORT
      LAYER Metal2 ;
        RECT 97.240 0.000 97.640 0.400 ;
    END
  END Tile_X0Y0_NN4END[9]
  PIN Tile_X0Y0_S1BEG[0]
    DIRECTION OUTPUT ;
    USE SIGNAL ;
    ANTENNADIFFAREA 2.724000 ;
    PORT
      LAYER Metal2 ;
        RECT 113.560 0.000 113.960 0.400 ;
    END
  END Tile_X0Y0_S1BEG[0]
  PIN Tile_X0Y0_S1BEG[1]
    DIRECTION OUTPUT ;
    USE SIGNAL ;
    ANTENNADIFFAREA 2.724000 ;
    PORT
      LAYER Metal2 ;
        RECT 115.480 0.000 115.880 0.400 ;
    END
  END Tile_X0Y0_S1BEG[1]
  PIN Tile_X0Y0_S1BEG[2]
    DIRECTION OUTPUT ;
    USE SIGNAL ;
    ANTENNADIFFAREA 2.724000 ;
    PORT
      LAYER Metal2 ;
        RECT 117.400 0.000 117.800 0.400 ;
    END
  END Tile_X0Y0_S1BEG[2]
  PIN Tile_X0Y0_S1BEG[3]
    DIRECTION OUTPUT ;
    USE SIGNAL ;
    ANTENNADIFFAREA 2.724000 ;
    PORT
      LAYER Metal2 ;
        RECT 119.320 0.000 119.720 0.400 ;
    END
  END Tile_X0Y0_S1BEG[3]
  PIN Tile_X0Y0_S2BEG[0]
    DIRECTION OUTPUT ;
    USE SIGNAL ;
    ANTENNADIFFAREA 2.724000 ;
    PORT
      LAYER Metal2 ;
        RECT 122.200 0.000 122.600 0.400 ;
    END
  END Tile_X0Y0_S2BEG[0]
  PIN Tile_X0Y0_S2BEG[1]
    DIRECTION OUTPUT ;
    USE SIGNAL ;
    ANTENNADIFFAREA 2.724000 ;
    PORT
      LAYER Metal2 ;
        RECT 124.120 0.000 124.520 0.400 ;
    END
  END Tile_X0Y0_S2BEG[1]
  PIN Tile_X0Y0_S2BEG[2]
    DIRECTION OUTPUT ;
    USE SIGNAL ;
    ANTENNADIFFAREA 2.724000 ;
    PORT
      LAYER Metal2 ;
        RECT 126.040 0.000 126.440 0.400 ;
    END
  END Tile_X0Y0_S2BEG[2]
  PIN Tile_X0Y0_S2BEG[3]
    DIRECTION OUTPUT ;
    USE SIGNAL ;
    ANTENNADIFFAREA 2.724000 ;
    PORT
      LAYER Metal2 ;
        RECT 127.960 0.000 128.360 0.400 ;
    END
  END Tile_X0Y0_S2BEG[3]
  PIN Tile_X0Y0_S2BEG[4]
    DIRECTION OUTPUT ;
    USE SIGNAL ;
    ANTENNADIFFAREA 2.724000 ;
    PORT
      LAYER Metal2 ;
        RECT 129.880 0.000 130.280 0.400 ;
    END
  END Tile_X0Y0_S2BEG[4]
  PIN Tile_X0Y0_S2BEG[5]
    DIRECTION OUTPUT ;
    USE SIGNAL ;
    ANTENNADIFFAREA 2.724000 ;
    PORT
      LAYER Metal2 ;
        RECT 131.800 0.000 132.200 0.400 ;
    END
  END Tile_X0Y0_S2BEG[5]
  PIN Tile_X0Y0_S2BEG[6]
    DIRECTION OUTPUT ;
    USE SIGNAL ;
    ANTENNADIFFAREA 2.724000 ;
    PORT
      LAYER Metal2 ;
        RECT 133.720 0.000 134.120 0.400 ;
    END
  END Tile_X0Y0_S2BEG[6]
  PIN Tile_X0Y0_S2BEG[7]
    DIRECTION OUTPUT ;
    USE SIGNAL ;
    ANTENNADIFFAREA 2.724000 ;
    PORT
      LAYER Metal2 ;
        RECT 135.640 0.000 136.040 0.400 ;
    END
  END Tile_X0Y0_S2BEG[7]
  PIN Tile_X0Y0_S2BEGb[0]
    DIRECTION OUTPUT ;
    USE SIGNAL ;
    ANTENNADIFFAREA 2.724000 ;
    PORT
      LAYER Metal2 ;
        RECT 139.480 0.000 139.880 0.400 ;
    END
  END Tile_X0Y0_S2BEGb[0]
  PIN Tile_X0Y0_S2BEGb[1]
    DIRECTION OUTPUT ;
    USE SIGNAL ;
    ANTENNADIFFAREA 2.724000 ;
    PORT
      LAYER Metal2 ;
        RECT 141.400 0.000 141.800 0.400 ;
    END
  END Tile_X0Y0_S2BEGb[1]
  PIN Tile_X0Y0_S2BEGb[2]
    DIRECTION OUTPUT ;
    USE SIGNAL ;
    ANTENNADIFFAREA 2.724000 ;
    PORT
      LAYER Metal2 ;
        RECT 143.320 0.000 143.720 0.400 ;
    END
  END Tile_X0Y0_S2BEGb[2]
  PIN Tile_X0Y0_S2BEGb[3]
    DIRECTION OUTPUT ;
    USE SIGNAL ;
    ANTENNADIFFAREA 2.724000 ;
    PORT
      LAYER Metal2 ;
        RECT 145.240 0.000 145.640 0.400 ;
    END
  END Tile_X0Y0_S2BEGb[3]
  PIN Tile_X0Y0_S2BEGb[4]
    DIRECTION OUTPUT ;
    USE SIGNAL ;
    ANTENNADIFFAREA 2.724000 ;
    PORT
      LAYER Metal2 ;
        RECT 147.160 0.000 147.560 0.400 ;
    END
  END Tile_X0Y0_S2BEGb[4]
  PIN Tile_X0Y0_S2BEGb[5]
    DIRECTION OUTPUT ;
    USE SIGNAL ;
    ANTENNADIFFAREA 2.724000 ;
    PORT
      LAYER Metal2 ;
        RECT 149.080 0.000 149.480 0.400 ;
    END
  END Tile_X0Y0_S2BEGb[5]
  PIN Tile_X0Y0_S2BEGb[6]
    DIRECTION OUTPUT ;
    USE SIGNAL ;
    ANTENNADIFFAREA 2.724000 ;
    PORT
      LAYER Metal2 ;
        RECT 151.000 0.000 151.400 0.400 ;
    END
  END Tile_X0Y0_S2BEGb[6]
  PIN Tile_X0Y0_S2BEGb[7]
    DIRECTION OUTPUT ;
    USE SIGNAL ;
    ANTENNADIFFAREA 2.724000 ;
    PORT
      LAYER Metal2 ;
        RECT 152.920 0.000 153.320 0.400 ;
    END
  END Tile_X0Y0_S2BEGb[7]
  PIN Tile_X0Y0_S4BEG[0]
    DIRECTION OUTPUT ;
    USE SIGNAL ;
    ANTENNADIFFAREA 2.724000 ;
    PORT
      LAYER Metal2 ;
        RECT 157.720 0.000 158.120 0.400 ;
    END
  END Tile_X0Y0_S4BEG[0]
  PIN Tile_X0Y0_S4BEG[10]
    DIRECTION OUTPUT ;
    USE SIGNAL ;
    ANTENNADIFFAREA 2.724000 ;
    PORT
      LAYER Metal2 ;
        RECT 176.920 0.000 177.320 0.400 ;
    END
  END Tile_X0Y0_S4BEG[10]
  PIN Tile_X0Y0_S4BEG[11]
    DIRECTION OUTPUT ;
    USE SIGNAL ;
    ANTENNADIFFAREA 2.724000 ;
    PORT
      LAYER Metal2 ;
        RECT 178.840 0.000 179.240 0.400 ;
    END
  END Tile_X0Y0_S4BEG[11]
  PIN Tile_X0Y0_S4BEG[12]
    DIRECTION OUTPUT ;
    USE SIGNAL ;
    ANTENNADIFFAREA 2.724000 ;
    PORT
      LAYER Metal2 ;
        RECT 180.760 0.000 181.160 0.400 ;
    END
  END Tile_X0Y0_S4BEG[12]
  PIN Tile_X0Y0_S4BEG[13]
    DIRECTION OUTPUT ;
    USE SIGNAL ;
    ANTENNADIFFAREA 2.724000 ;
    PORT
      LAYER Metal2 ;
        RECT 182.680 0.000 183.080 0.400 ;
    END
  END Tile_X0Y0_S4BEG[13]
  PIN Tile_X0Y0_S4BEG[14]
    DIRECTION OUTPUT ;
    USE SIGNAL ;
    ANTENNADIFFAREA 2.724000 ;
    PORT
      LAYER Metal2 ;
        RECT 184.600 0.000 185.000 0.400 ;
    END
  END Tile_X0Y0_S4BEG[14]
  PIN Tile_X0Y0_S4BEG[15]
    DIRECTION OUTPUT ;
    USE SIGNAL ;
    ANTENNADIFFAREA 2.724000 ;
    PORT
      LAYER Metal2 ;
        RECT 186.520 0.000 186.920 0.400 ;
    END
  END Tile_X0Y0_S4BEG[15]
  PIN Tile_X0Y0_S4BEG[1]
    DIRECTION OUTPUT ;
    USE SIGNAL ;
    ANTENNADIFFAREA 2.724000 ;
    PORT
      LAYER Metal2 ;
        RECT 159.640 0.000 160.040 0.400 ;
    END
  END Tile_X0Y0_S4BEG[1]
  PIN Tile_X0Y0_S4BEG[2]
    DIRECTION OUTPUT ;
    USE SIGNAL ;
    ANTENNADIFFAREA 2.724000 ;
    PORT
      LAYER Metal2 ;
        RECT 161.560 0.000 161.960 0.400 ;
    END
  END Tile_X0Y0_S4BEG[2]
  PIN Tile_X0Y0_S4BEG[3]
    DIRECTION OUTPUT ;
    USE SIGNAL ;
    ANTENNADIFFAREA 2.724000 ;
    PORT
      LAYER Metal2 ;
        RECT 163.480 0.000 163.880 0.400 ;
    END
  END Tile_X0Y0_S4BEG[3]
  PIN Tile_X0Y0_S4BEG[4]
    DIRECTION OUTPUT ;
    USE SIGNAL ;
    ANTENNADIFFAREA 2.724000 ;
    PORT
      LAYER Metal2 ;
        RECT 165.400 0.000 165.800 0.400 ;
    END
  END Tile_X0Y0_S4BEG[4]
  PIN Tile_X0Y0_S4BEG[5]
    DIRECTION OUTPUT ;
    USE SIGNAL ;
    ANTENNADIFFAREA 2.724000 ;
    PORT
      LAYER Metal2 ;
        RECT 167.320 0.000 167.720 0.400 ;
    END
  END Tile_X0Y0_S4BEG[5]
  PIN Tile_X0Y0_S4BEG[6]
    DIRECTION OUTPUT ;
    USE SIGNAL ;
    ANTENNADIFFAREA 2.724000 ;
    PORT
      LAYER Metal2 ;
        RECT 169.240 0.000 169.640 0.400 ;
    END
  END Tile_X0Y0_S4BEG[6]
  PIN Tile_X0Y0_S4BEG[7]
    DIRECTION OUTPUT ;
    USE SIGNAL ;
    ANTENNADIFFAREA 2.724000 ;
    PORT
      LAYER Metal2 ;
        RECT 171.160 0.000 171.560 0.400 ;
    END
  END Tile_X0Y0_S4BEG[7]
  PIN Tile_X0Y0_S4BEG[8]
    DIRECTION OUTPUT ;
    USE SIGNAL ;
    ANTENNADIFFAREA 2.724000 ;
    PORT
      LAYER Metal2 ;
        RECT 173.080 0.000 173.480 0.400 ;
    END
  END Tile_X0Y0_S4BEG[8]
  PIN Tile_X0Y0_S4BEG[9]
    DIRECTION OUTPUT ;
    USE SIGNAL ;
    ANTENNADIFFAREA 2.724000 ;
    PORT
      LAYER Metal2 ;
        RECT 175.000 0.000 175.400 0.400 ;
    END
  END Tile_X0Y0_S4BEG[9]
  PIN Tile_X0Y0_SS4BEG[0]
    DIRECTION OUTPUT ;
    USE SIGNAL ;
    ANTENNADIFFAREA 2.724000 ;
    PORT
      LAYER Metal2 ;
        RECT 192.280 0.000 192.680 0.400 ;
    END
  END Tile_X0Y0_SS4BEG[0]
  PIN Tile_X0Y0_SS4BEG[10]
    DIRECTION OUTPUT ;
    USE SIGNAL ;
    ANTENNADIFFAREA 2.724000 ;
    PORT
      LAYER Metal2 ;
        RECT 211.480 0.000 211.880 0.400 ;
    END
  END Tile_X0Y0_SS4BEG[10]
  PIN Tile_X0Y0_SS4BEG[11]
    DIRECTION OUTPUT ;
    USE SIGNAL ;
    ANTENNADIFFAREA 2.724000 ;
    PORT
      LAYER Metal2 ;
        RECT 213.400 0.000 213.800 0.400 ;
    END
  END Tile_X0Y0_SS4BEG[11]
  PIN Tile_X0Y0_SS4BEG[12]
    DIRECTION OUTPUT ;
    USE SIGNAL ;
    ANTENNADIFFAREA 2.724000 ;
    PORT
      LAYER Metal2 ;
        RECT 215.320 0.000 215.720 0.400 ;
    END
  END Tile_X0Y0_SS4BEG[12]
  PIN Tile_X0Y0_SS4BEG[13]
    DIRECTION OUTPUT ;
    USE SIGNAL ;
    ANTENNADIFFAREA 2.724000 ;
    PORT
      LAYER Metal2 ;
        RECT 217.240 0.000 217.640 0.400 ;
    END
  END Tile_X0Y0_SS4BEG[13]
  PIN Tile_X0Y0_SS4BEG[14]
    DIRECTION OUTPUT ;
    USE SIGNAL ;
    ANTENNADIFFAREA 2.724000 ;
    PORT
      LAYER Metal2 ;
        RECT 219.160 0.000 219.560 0.400 ;
    END
  END Tile_X0Y0_SS4BEG[14]
  PIN Tile_X0Y0_SS4BEG[15]
    DIRECTION OUTPUT ;
    USE SIGNAL ;
    ANTENNADIFFAREA 2.724000 ;
    PORT
      LAYER Metal2 ;
        RECT 221.080 0.000 221.480 0.400 ;
    END
  END Tile_X0Y0_SS4BEG[15]
  PIN Tile_X0Y0_SS4BEG[1]
    DIRECTION OUTPUT ;
    USE SIGNAL ;
    ANTENNADIFFAREA 2.724000 ;
    PORT
      LAYER Metal2 ;
        RECT 194.200 0.000 194.600 0.400 ;
    END
  END Tile_X0Y0_SS4BEG[1]
  PIN Tile_X0Y0_SS4BEG[2]
    DIRECTION OUTPUT ;
    USE SIGNAL ;
    ANTENNADIFFAREA 2.724000 ;
    PORT
      LAYER Metal2 ;
        RECT 196.120 0.000 196.520 0.400 ;
    END
  END Tile_X0Y0_SS4BEG[2]
  PIN Tile_X0Y0_SS4BEG[3]
    DIRECTION OUTPUT ;
    USE SIGNAL ;
    ANTENNADIFFAREA 2.724000 ;
    PORT
      LAYER Metal2 ;
        RECT 198.040 0.000 198.440 0.400 ;
    END
  END Tile_X0Y0_SS4BEG[3]
  PIN Tile_X0Y0_SS4BEG[4]
    DIRECTION OUTPUT ;
    USE SIGNAL ;
    ANTENNADIFFAREA 2.724000 ;
    PORT
      LAYER Metal2 ;
        RECT 199.960 0.000 200.360 0.400 ;
    END
  END Tile_X0Y0_SS4BEG[4]
  PIN Tile_X0Y0_SS4BEG[5]
    DIRECTION OUTPUT ;
    USE SIGNAL ;
    ANTENNADIFFAREA 2.724000 ;
    PORT
      LAYER Metal2 ;
        RECT 201.880 0.000 202.280 0.400 ;
    END
  END Tile_X0Y0_SS4BEG[5]
  PIN Tile_X0Y0_SS4BEG[6]
    DIRECTION OUTPUT ;
    USE SIGNAL ;
    ANTENNADIFFAREA 2.724000 ;
    PORT
      LAYER Metal2 ;
        RECT 203.800 0.000 204.200 0.400 ;
    END
  END Tile_X0Y0_SS4BEG[6]
  PIN Tile_X0Y0_SS4BEG[7]
    DIRECTION OUTPUT ;
    USE SIGNAL ;
    ANTENNADIFFAREA 2.724000 ;
    PORT
      LAYER Metal2 ;
        RECT 205.720 0.000 206.120 0.400 ;
    END
  END Tile_X0Y0_SS4BEG[7]
  PIN Tile_X0Y0_SS4BEG[8]
    DIRECTION OUTPUT ;
    USE SIGNAL ;
    ANTENNADIFFAREA 2.724000 ;
    PORT
      LAYER Metal2 ;
        RECT 207.640 0.000 208.040 0.400 ;
    END
  END Tile_X0Y0_SS4BEG[8]
  PIN Tile_X0Y0_SS4BEG[9]
    DIRECTION OUTPUT ;
    USE SIGNAL ;
    ANTENNADIFFAREA 2.724000 ;
    PORT
      LAYER Metal2 ;
        RECT 209.560 0.000 209.960 0.400 ;
    END
  END Tile_X0Y0_SS4BEG[9]
  PIN Tile_X0Y0_UserCLK
    DIRECTION INPUT ;
    USE SIGNAL ;
    ANTENNAGATEAREA 9.127299 ;
    PORT
      LAYER Metal3 ;
        RECT 0.000 1.900 0.400 2.300 ;
    END
  END Tile_X0Y0_UserCLK
  PIN Tile_X1Y0_Ci
    DIRECTION INPUT ;
    USE SIGNAL ;
    PORT
      LAYER Metal2 ;
        RECT 496.120 0.000 496.520 0.400 ;
    END
  END Tile_X1Y0_Ci
  PIN Tile_X1Y0_FrameData_O[0]
    DIRECTION OUTPUT ;
    USE SIGNAL ;
    ANTENNADIFFAREA 2.724000 ;
    PORT
      LAYER Metal3 ;
        RECT 540.080 12.820 540.480 13.220 ;
    END
  END Tile_X1Y0_FrameData_O[0]
  PIN Tile_X1Y0_FrameData_O[10]
    DIRECTION OUTPUT ;
    USE SIGNAL ;
    ANTENNADIFFAREA 2.724000 ;
    PORT
      LAYER Metal3 ;
        RECT 540.080 29.620 540.480 30.020 ;
    END
  END Tile_X1Y0_FrameData_O[10]
  PIN Tile_X1Y0_FrameData_O[11]
    DIRECTION OUTPUT ;
    USE SIGNAL ;
    ANTENNADIFFAREA 2.724000 ;
    PORT
      LAYER Metal3 ;
        RECT 540.080 31.300 540.480 31.700 ;
    END
  END Tile_X1Y0_FrameData_O[11]
  PIN Tile_X1Y0_FrameData_O[12]
    DIRECTION OUTPUT ;
    USE SIGNAL ;
    ANTENNADIFFAREA 2.724000 ;
    PORT
      LAYER Metal3 ;
        RECT 540.080 32.980 540.480 33.380 ;
    END
  END Tile_X1Y0_FrameData_O[12]
  PIN Tile_X1Y0_FrameData_O[13]
    DIRECTION OUTPUT ;
    USE SIGNAL ;
    ANTENNADIFFAREA 2.724000 ;
    PORT
      LAYER Metal3 ;
        RECT 540.080 34.660 540.480 35.060 ;
    END
  END Tile_X1Y0_FrameData_O[13]
  PIN Tile_X1Y0_FrameData_O[14]
    DIRECTION OUTPUT ;
    USE SIGNAL ;
    ANTENNADIFFAREA 2.724000 ;
    PORT
      LAYER Metal3 ;
        RECT 540.080 36.340 540.480 36.740 ;
    END
  END Tile_X1Y0_FrameData_O[14]
  PIN Tile_X1Y0_FrameData_O[15]
    DIRECTION OUTPUT ;
    USE SIGNAL ;
    ANTENNADIFFAREA 2.724000 ;
    PORT
      LAYER Metal3 ;
        RECT 540.080 38.020 540.480 38.420 ;
    END
  END Tile_X1Y0_FrameData_O[15]
  PIN Tile_X1Y0_FrameData_O[16]
    DIRECTION OUTPUT ;
    USE SIGNAL ;
    ANTENNADIFFAREA 2.724000 ;
    PORT
      LAYER Metal3 ;
        RECT 540.080 39.700 540.480 40.100 ;
    END
  END Tile_X1Y0_FrameData_O[16]
  PIN Tile_X1Y0_FrameData_O[17]
    DIRECTION OUTPUT ;
    USE SIGNAL ;
    ANTENNADIFFAREA 2.724000 ;
    PORT
      LAYER Metal3 ;
        RECT 540.080 41.380 540.480 41.780 ;
    END
  END Tile_X1Y0_FrameData_O[17]
  PIN Tile_X1Y0_FrameData_O[18]
    DIRECTION OUTPUT ;
    USE SIGNAL ;
    ANTENNADIFFAREA 2.724000 ;
    PORT
      LAYER Metal3 ;
        RECT 540.080 43.060 540.480 43.460 ;
    END
  END Tile_X1Y0_FrameData_O[18]
  PIN Tile_X1Y0_FrameData_O[19]
    DIRECTION OUTPUT ;
    USE SIGNAL ;
    ANTENNADIFFAREA 2.724000 ;
    PORT
      LAYER Metal3 ;
        RECT 540.080 44.740 540.480 45.140 ;
    END
  END Tile_X1Y0_FrameData_O[19]
  PIN Tile_X1Y0_FrameData_O[1]
    DIRECTION OUTPUT ;
    USE SIGNAL ;
    ANTENNADIFFAREA 2.724000 ;
    PORT
      LAYER Metal3 ;
        RECT 540.080 14.500 540.480 14.900 ;
    END
  END Tile_X1Y0_FrameData_O[1]
  PIN Tile_X1Y0_FrameData_O[20]
    DIRECTION OUTPUT ;
    USE SIGNAL ;
    ANTENNADIFFAREA 2.724000 ;
    PORT
      LAYER Metal3 ;
        RECT 540.080 46.420 540.480 46.820 ;
    END
  END Tile_X1Y0_FrameData_O[20]
  PIN Tile_X1Y0_FrameData_O[21]
    DIRECTION OUTPUT ;
    USE SIGNAL ;
    ANTENNADIFFAREA 2.724000 ;
    PORT
      LAYER Metal3 ;
        RECT 540.080 48.100 540.480 48.500 ;
    END
  END Tile_X1Y0_FrameData_O[21]
  PIN Tile_X1Y0_FrameData_O[22]
    DIRECTION OUTPUT ;
    USE SIGNAL ;
    ANTENNADIFFAREA 2.724000 ;
    PORT
      LAYER Metal3 ;
        RECT 540.080 49.780 540.480 50.180 ;
    END
  END Tile_X1Y0_FrameData_O[22]
  PIN Tile_X1Y0_FrameData_O[23]
    DIRECTION OUTPUT ;
    USE SIGNAL ;
    ANTENNADIFFAREA 2.724000 ;
    PORT
      LAYER Metal3 ;
        RECT 540.080 51.460 540.480 51.860 ;
    END
  END Tile_X1Y0_FrameData_O[23]
  PIN Tile_X1Y0_FrameData_O[24]
    DIRECTION OUTPUT ;
    USE SIGNAL ;
    ANTENNADIFFAREA 2.724000 ;
    PORT
      LAYER Metal3 ;
        RECT 540.080 53.140 540.480 53.540 ;
    END
  END Tile_X1Y0_FrameData_O[24]
  PIN Tile_X1Y0_FrameData_O[25]
    DIRECTION OUTPUT ;
    USE SIGNAL ;
    ANTENNADIFFAREA 2.724000 ;
    PORT
      LAYER Metal3 ;
        RECT 540.080 54.820 540.480 55.220 ;
    END
  END Tile_X1Y0_FrameData_O[25]
  PIN Tile_X1Y0_FrameData_O[26]
    DIRECTION OUTPUT ;
    USE SIGNAL ;
    ANTENNADIFFAREA 2.724000 ;
    PORT
      LAYER Metal3 ;
        RECT 540.080 56.500 540.480 56.900 ;
    END
  END Tile_X1Y0_FrameData_O[26]
  PIN Tile_X1Y0_FrameData_O[27]
    DIRECTION OUTPUT ;
    USE SIGNAL ;
    ANTENNADIFFAREA 2.724000 ;
    PORT
      LAYER Metal3 ;
        RECT 540.080 58.180 540.480 58.580 ;
    END
  END Tile_X1Y0_FrameData_O[27]
  PIN Tile_X1Y0_FrameData_O[28]
    DIRECTION OUTPUT ;
    USE SIGNAL ;
    ANTENNADIFFAREA 2.724000 ;
    PORT
      LAYER Metal3 ;
        RECT 540.080 59.860 540.480 60.260 ;
    END
  END Tile_X1Y0_FrameData_O[28]
  PIN Tile_X1Y0_FrameData_O[29]
    DIRECTION OUTPUT ;
    USE SIGNAL ;
    ANTENNADIFFAREA 2.724000 ;
    PORT
      LAYER Metal3 ;
        RECT 540.080 61.540 540.480 61.940 ;
    END
  END Tile_X1Y0_FrameData_O[29]
  PIN Tile_X1Y0_FrameData_O[2]
    DIRECTION OUTPUT ;
    USE SIGNAL ;
    ANTENNADIFFAREA 2.724000 ;
    PORT
      LAYER Metal3 ;
        RECT 540.080 16.180 540.480 16.580 ;
    END
  END Tile_X1Y0_FrameData_O[2]
  PIN Tile_X1Y0_FrameData_O[30]
    DIRECTION OUTPUT ;
    USE SIGNAL ;
    ANTENNADIFFAREA 2.724000 ;
    PORT
      LAYER Metal3 ;
        RECT 540.080 63.220 540.480 63.620 ;
    END
  END Tile_X1Y0_FrameData_O[30]
  PIN Tile_X1Y0_FrameData_O[31]
    DIRECTION OUTPUT ;
    USE SIGNAL ;
    ANTENNADIFFAREA 2.724000 ;
    PORT
      LAYER Metal3 ;
        RECT 540.080 64.900 540.480 65.300 ;
    END
  END Tile_X1Y0_FrameData_O[31]
  PIN Tile_X1Y0_FrameData_O[3]
    DIRECTION OUTPUT ;
    USE SIGNAL ;
    ANTENNADIFFAREA 2.724000 ;
    PORT
      LAYER Metal3 ;
        RECT 540.080 17.860 540.480 18.260 ;
    END
  END Tile_X1Y0_FrameData_O[3]
  PIN Tile_X1Y0_FrameData_O[4]
    DIRECTION OUTPUT ;
    USE SIGNAL ;
    ANTENNADIFFAREA 2.724000 ;
    PORT
      LAYER Metal3 ;
        RECT 540.080 19.540 540.480 19.940 ;
    END
  END Tile_X1Y0_FrameData_O[4]
  PIN Tile_X1Y0_FrameData_O[5]
    DIRECTION OUTPUT ;
    USE SIGNAL ;
    ANTENNADIFFAREA 2.724000 ;
    PORT
      LAYER Metal3 ;
        RECT 540.080 21.220 540.480 21.620 ;
    END
  END Tile_X1Y0_FrameData_O[5]
  PIN Tile_X1Y0_FrameData_O[6]
    DIRECTION OUTPUT ;
    USE SIGNAL ;
    ANTENNADIFFAREA 2.724000 ;
    PORT
      LAYER Metal3 ;
        RECT 540.080 22.900 540.480 23.300 ;
    END
  END Tile_X1Y0_FrameData_O[6]
  PIN Tile_X1Y0_FrameData_O[7]
    DIRECTION OUTPUT ;
    USE SIGNAL ;
    ANTENNADIFFAREA 2.724000 ;
    PORT
      LAYER Metal3 ;
        RECT 540.080 24.580 540.480 24.980 ;
    END
  END Tile_X1Y0_FrameData_O[7]
  PIN Tile_X1Y0_FrameData_O[8]
    DIRECTION OUTPUT ;
    USE SIGNAL ;
    ANTENNADIFFAREA 2.724000 ;
    PORT
      LAYER Metal3 ;
        RECT 540.080 26.260 540.480 26.660 ;
    END
  END Tile_X1Y0_FrameData_O[8]
  PIN Tile_X1Y0_FrameData_O[9]
    DIRECTION OUTPUT ;
    USE SIGNAL ;
    ANTENNADIFFAREA 2.724000 ;
    PORT
      LAYER Metal3 ;
        RECT 540.080 27.940 540.480 28.340 ;
    END
  END Tile_X1Y0_FrameData_O[9]
  PIN Tile_X1Y0_FrameStrobe[0]
    DIRECTION INPUT ;
    USE SIGNAL ;
    ANTENNAGATEAREA 11.745500 ;
    PORT
      LAYER Metal2 ;
        RECT 500.920 0.000 501.320 0.400 ;
    END
  END Tile_X1Y0_FrameStrobe[0]
  PIN Tile_X1Y0_FrameStrobe[10]
    DIRECTION INPUT ;
    USE SIGNAL ;
    ANTENNAGATEAREA 0.180700 ;
    ANTENNADIFFAREA 2.015400 ;
    PORT
      LAYER Metal2 ;
        RECT 520.120 0.000 520.520 0.400 ;
    END
  END Tile_X1Y0_FrameStrobe[10]
  PIN Tile_X1Y0_FrameStrobe[11]
    DIRECTION INPUT ;
    USE SIGNAL ;
    ANTENNAGATEAREA 0.180700 ;
    ANTENNADIFFAREA 2.015400 ;
    PORT
      LAYER Metal2 ;
        RECT 522.040 0.000 522.440 0.400 ;
    END
  END Tile_X1Y0_FrameStrobe[11]
  PIN Tile_X1Y0_FrameStrobe[12]
    DIRECTION INPUT ;
    USE SIGNAL ;
    ANTENNAGATEAREA 0.180700 ;
    ANTENNADIFFAREA 2.015400 ;
    PORT
      LAYER Metal2 ;
        RECT 523.960 0.000 524.360 0.400 ;
    END
  END Tile_X1Y0_FrameStrobe[12]
  PIN Tile_X1Y0_FrameStrobe[13]
    DIRECTION INPUT ;
    USE SIGNAL ;
    ANTENNAGATEAREA 0.180700 ;
    PORT
      LAYER Metal2 ;
        RECT 525.880 0.000 526.280 0.400 ;
    END
  END Tile_X1Y0_FrameStrobe[13]
  PIN Tile_X1Y0_FrameStrobe[14]
    DIRECTION INPUT ;
    USE SIGNAL ;
    ANTENNAGATEAREA 0.180700 ;
    ANTENNADIFFAREA 2.015400 ;
    PORT
      LAYER Metal2 ;
        RECT 527.800 0.000 528.200 0.400 ;
    END
  END Tile_X1Y0_FrameStrobe[14]
  PIN Tile_X1Y0_FrameStrobe[15]
    DIRECTION INPUT ;
    USE SIGNAL ;
    ANTENNAGATEAREA 0.180700 ;
    ANTENNADIFFAREA 4.030800 ;
    PORT
      LAYER Metal2 ;
        RECT 529.720 0.000 530.120 0.400 ;
    END
  END Tile_X1Y0_FrameStrobe[15]
  PIN Tile_X1Y0_FrameStrobe[16]
    DIRECTION INPUT ;
    USE SIGNAL ;
    ANTENNAGATEAREA 0.180700 ;
    PORT
      LAYER Metal2 ;
        RECT 531.640 0.000 532.040 0.400 ;
    END
  END Tile_X1Y0_FrameStrobe[16]
  PIN Tile_X1Y0_FrameStrobe[17]
    DIRECTION INPUT ;
    USE SIGNAL ;
    ANTENNAGATEAREA 0.180700 ;
    ANTENNADIFFAREA 2.015400 ;
    PORT
      LAYER Metal2 ;
        RECT 533.560 0.000 533.960 0.400 ;
    END
  END Tile_X1Y0_FrameStrobe[17]
  PIN Tile_X1Y0_FrameStrobe[18]
    DIRECTION INPUT ;
    USE SIGNAL ;
    ANTENNAGATEAREA 0.180700 ;
    ANTENNADIFFAREA 2.015400 ;
    PORT
      LAYER Metal2 ;
        RECT 535.480 0.000 535.880 0.400 ;
    END
  END Tile_X1Y0_FrameStrobe[18]
  PIN Tile_X1Y0_FrameStrobe[19]
    DIRECTION INPUT ;
    USE SIGNAL ;
    ANTENNAGATEAREA 0.180700 ;
    ANTENNADIFFAREA 2.015400 ;
    PORT
      LAYER Metal2 ;
        RECT 537.400 0.000 537.800 0.400 ;
    END
  END Tile_X1Y0_FrameStrobe[19]
  PIN Tile_X1Y0_FrameStrobe[1]
    DIRECTION INPUT ;
    USE SIGNAL ;
    ANTENNAGATEAREA 2.710500 ;
    PORT
      LAYER Metal2 ;
        RECT 502.840 0.000 503.240 0.400 ;
    END
  END Tile_X1Y0_FrameStrobe[1]
  PIN Tile_X1Y0_FrameStrobe[2]
    DIRECTION INPUT ;
    USE SIGNAL ;
    ANTENNAGATEAREA 0.180700 ;
    PORT
      LAYER Metal2 ;
        RECT 504.760 0.000 505.160 0.400 ;
    END
  END Tile_X1Y0_FrameStrobe[2]
  PIN Tile_X1Y0_FrameStrobe[3]
    DIRECTION INPUT ;
    USE SIGNAL ;
    ANTENNAGATEAREA 0.180700 ;
    ANTENNADIFFAREA 2.015400 ;
    PORT
      LAYER Metal2 ;
        RECT 506.680 0.000 507.080 0.400 ;
    END
  END Tile_X1Y0_FrameStrobe[3]
  PIN Tile_X1Y0_FrameStrobe[4]
    DIRECTION INPUT ;
    USE SIGNAL ;
    ANTENNAGATEAREA 0.180700 ;
    PORT
      LAYER Metal2 ;
        RECT 508.600 0.000 509.000 0.400 ;
    END
  END Tile_X1Y0_FrameStrobe[4]
  PIN Tile_X1Y0_FrameStrobe[5]
    DIRECTION INPUT ;
    USE SIGNAL ;
    ANTENNAGATEAREA 0.180700 ;
    ANTENNADIFFAREA 2.015400 ;
    PORT
      LAYER Metal2 ;
        RECT 510.520 0.000 510.920 0.400 ;
    END
  END Tile_X1Y0_FrameStrobe[5]
  PIN Tile_X1Y0_FrameStrobe[6]
    DIRECTION INPUT ;
    USE SIGNAL ;
    ANTENNAGATEAREA 0.180700 ;
    ANTENNADIFFAREA 2.015400 ;
    PORT
      LAYER Metal2 ;
        RECT 512.440 0.000 512.840 0.400 ;
    END
  END Tile_X1Y0_FrameStrobe[6]
  PIN Tile_X1Y0_FrameStrobe[7]
    DIRECTION INPUT ;
    USE SIGNAL ;
    ANTENNAGATEAREA 0.180700 ;
    PORT
      LAYER Metal2 ;
        RECT 514.360 0.000 514.760 0.400 ;
    END
  END Tile_X1Y0_FrameStrobe[7]
  PIN Tile_X1Y0_FrameStrobe[8]
    DIRECTION INPUT ;
    USE SIGNAL ;
    ANTENNAGATEAREA 0.180700 ;
    PORT
      LAYER Metal2 ;
        RECT 516.280 0.000 516.680 0.400 ;
    END
  END Tile_X1Y0_FrameStrobe[8]
  PIN Tile_X1Y0_FrameStrobe[9]
    DIRECTION INPUT ;
    USE SIGNAL ;
    ANTENNAGATEAREA 0.180700 ;
    PORT
      LAYER Metal2 ;
        RECT 518.200 0.000 518.600 0.400 ;
    END
  END Tile_X1Y0_FrameStrobe[9]
  PIN Tile_X1Y0_FrameStrobe_O[0]
    DIRECTION OUTPUT ;
    USE SIGNAL ;
    ANTENNADIFFAREA 2.724000 ;
    PORT
      LAYER Metal2 ;
        RECT 281.080 74.780 281.480 75.180 ;
    END
  END Tile_X1Y0_FrameStrobe_O[0]
  PIN Tile_X1Y0_FrameStrobe_O[10]
    DIRECTION OUTPUT ;
    USE SIGNAL ;
    ANTENNADIFFAREA 2.724000 ;
    PORT
      LAYER Metal2 ;
        RECT 319.480 74.780 319.880 75.180 ;
    END
  END Tile_X1Y0_FrameStrobe_O[10]
  PIN Tile_X1Y0_FrameStrobe_O[11]
    DIRECTION OUTPUT ;
    USE SIGNAL ;
    ANTENNADIFFAREA 2.724000 ;
    PORT
      LAYER Metal2 ;
        RECT 323.320 74.780 323.720 75.180 ;
    END
  END Tile_X1Y0_FrameStrobe_O[11]
  PIN Tile_X1Y0_FrameStrobe_O[12]
    DIRECTION OUTPUT ;
    USE SIGNAL ;
    ANTENNADIFFAREA 2.724000 ;
    PORT
      LAYER Metal2 ;
        RECT 327.160 74.780 327.560 75.180 ;
    END
  END Tile_X1Y0_FrameStrobe_O[12]
  PIN Tile_X1Y0_FrameStrobe_O[13]
    DIRECTION OUTPUT ;
    USE SIGNAL ;
    ANTENNADIFFAREA 2.724000 ;
    PORT
      LAYER Metal2 ;
        RECT 331.000 74.780 331.400 75.180 ;
    END
  END Tile_X1Y0_FrameStrobe_O[13]
  PIN Tile_X1Y0_FrameStrobe_O[14]
    DIRECTION OUTPUT ;
    USE SIGNAL ;
    ANTENNADIFFAREA 2.724000 ;
    PORT
      LAYER Metal2 ;
        RECT 334.840 74.780 335.240 75.180 ;
    END
  END Tile_X1Y0_FrameStrobe_O[14]
  PIN Tile_X1Y0_FrameStrobe_O[15]
    DIRECTION OUTPUT ;
    USE SIGNAL ;
    ANTENNADIFFAREA 2.724000 ;
    PORT
      LAYER Metal2 ;
        RECT 338.680 74.780 339.080 75.180 ;
    END
  END Tile_X1Y0_FrameStrobe_O[15]
  PIN Tile_X1Y0_FrameStrobe_O[16]
    DIRECTION OUTPUT ;
    USE SIGNAL ;
    ANTENNADIFFAREA 2.724000 ;
    PORT
      LAYER Metal2 ;
        RECT 342.520 74.780 342.920 75.180 ;
    END
  END Tile_X1Y0_FrameStrobe_O[16]
  PIN Tile_X1Y0_FrameStrobe_O[17]
    DIRECTION OUTPUT ;
    USE SIGNAL ;
    ANTENNADIFFAREA 2.724000 ;
    PORT
      LAYER Metal2 ;
        RECT 346.360 74.780 346.760 75.180 ;
    END
  END Tile_X1Y0_FrameStrobe_O[17]
  PIN Tile_X1Y0_FrameStrobe_O[18]
    DIRECTION OUTPUT ;
    USE SIGNAL ;
    ANTENNADIFFAREA 2.724000 ;
    PORT
      LAYER Metal2 ;
        RECT 350.200 74.780 350.600 75.180 ;
    END
  END Tile_X1Y0_FrameStrobe_O[18]
  PIN Tile_X1Y0_FrameStrobe_O[19]
    DIRECTION OUTPUT ;
    USE SIGNAL ;
    ANTENNADIFFAREA 2.724000 ;
    PORT
      LAYER Metal2 ;
        RECT 354.040 74.780 354.440 75.180 ;
    END
  END Tile_X1Y0_FrameStrobe_O[19]
  PIN Tile_X1Y0_FrameStrobe_O[1]
    DIRECTION OUTPUT ;
    USE SIGNAL ;
    ANTENNADIFFAREA 2.724000 ;
    PORT
      LAYER Metal2 ;
        RECT 284.920 74.780 285.320 75.180 ;
    END
  END Tile_X1Y0_FrameStrobe_O[1]
  PIN Tile_X1Y0_FrameStrobe_O[2]
    DIRECTION OUTPUT ;
    USE SIGNAL ;
    ANTENNADIFFAREA 2.724000 ;
    PORT
      LAYER Metal2 ;
        RECT 288.760 74.780 289.160 75.180 ;
    END
  END Tile_X1Y0_FrameStrobe_O[2]
  PIN Tile_X1Y0_FrameStrobe_O[3]
    DIRECTION OUTPUT ;
    USE SIGNAL ;
    ANTENNADIFFAREA 2.724000 ;
    PORT
      LAYER Metal2 ;
        RECT 292.600 74.780 293.000 75.180 ;
    END
  END Tile_X1Y0_FrameStrobe_O[3]
  PIN Tile_X1Y0_FrameStrobe_O[4]
    DIRECTION OUTPUT ;
    USE SIGNAL ;
    ANTENNADIFFAREA 2.724000 ;
    PORT
      LAYER Metal2 ;
        RECT 296.440 74.780 296.840 75.180 ;
    END
  END Tile_X1Y0_FrameStrobe_O[4]
  PIN Tile_X1Y0_FrameStrobe_O[5]
    DIRECTION OUTPUT ;
    USE SIGNAL ;
    ANTENNADIFFAREA 2.724000 ;
    PORT
      LAYER Metal2 ;
        RECT 300.280 74.780 300.680 75.180 ;
    END
  END Tile_X1Y0_FrameStrobe_O[5]
  PIN Tile_X1Y0_FrameStrobe_O[6]
    DIRECTION OUTPUT ;
    USE SIGNAL ;
    ANTENNADIFFAREA 2.724000 ;
    PORT
      LAYER Metal2 ;
        RECT 304.120 74.780 304.520 75.180 ;
    END
  END Tile_X1Y0_FrameStrobe_O[6]
  PIN Tile_X1Y0_FrameStrobe_O[7]
    DIRECTION OUTPUT ;
    USE SIGNAL ;
    ANTENNADIFFAREA 2.724000 ;
    PORT
      LAYER Metal2 ;
        RECT 307.960 74.780 308.360 75.180 ;
    END
  END Tile_X1Y0_FrameStrobe_O[7]
  PIN Tile_X1Y0_FrameStrobe_O[8]
    DIRECTION OUTPUT ;
    USE SIGNAL ;
    ANTENNADIFFAREA 2.724000 ;
    PORT
      LAYER Metal2 ;
        RECT 311.800 74.780 312.200 75.180 ;
    END
  END Tile_X1Y0_FrameStrobe_O[8]
  PIN Tile_X1Y0_FrameStrobe_O[9]
    DIRECTION OUTPUT ;
    USE SIGNAL ;
    ANTENNADIFFAREA 2.724000 ;
    PORT
      LAYER Metal2 ;
        RECT 315.640 74.780 316.040 75.180 ;
    END
  END Tile_X1Y0_FrameStrobe_O[9]
  PIN Tile_X1Y0_N1END[0]
    DIRECTION INPUT ;
    USE SIGNAL ;
    ANTENNAGATEAREA 0.393900 ;
    PORT
      LAYER Metal2 ;
        RECT 272.440 0.000 272.840 0.400 ;
    END
  END Tile_X1Y0_N1END[0]
  PIN Tile_X1Y0_N1END[1]
    DIRECTION INPUT ;
    USE SIGNAL ;
    ANTENNAGATEAREA 0.393900 ;
    PORT
      LAYER Metal2 ;
        RECT 274.360 0.000 274.760 0.400 ;
    END
  END Tile_X1Y0_N1END[1]
  PIN Tile_X1Y0_N1END[2]
    DIRECTION INPUT ;
    USE SIGNAL ;
    ANTENNAGATEAREA 0.393900 ;
    PORT
      LAYER Metal2 ;
        RECT 276.280 0.000 276.680 0.400 ;
    END
  END Tile_X1Y0_N1END[2]
  PIN Tile_X1Y0_N1END[3]
    DIRECTION INPUT ;
    USE SIGNAL ;
    ANTENNAGATEAREA 0.393900 ;
    PORT
      LAYER Metal2 ;
        RECT 278.200 0.000 278.600 0.400 ;
    END
  END Tile_X1Y0_N1END[3]
  PIN Tile_X1Y0_N2END[0]
    DIRECTION INPUT ;
    USE SIGNAL ;
    ANTENNAGATEAREA 0.180700 ;
    PORT
      LAYER Metal2 ;
        RECT 297.400 0.000 297.800 0.400 ;
    END
  END Tile_X1Y0_N2END[0]
  PIN Tile_X1Y0_N2END[1]
    DIRECTION INPUT ;
    USE SIGNAL ;
    ANTENNAGATEAREA 0.180700 ;
    PORT
      LAYER Metal2 ;
        RECT 299.320 0.000 299.720 0.400 ;
    END
  END Tile_X1Y0_N2END[1]
  PIN Tile_X1Y0_N2END[2]
    DIRECTION INPUT ;
    USE SIGNAL ;
    ANTENNAGATEAREA 0.180700 ;
    PORT
      LAYER Metal2 ;
        RECT 301.240 0.000 301.640 0.400 ;
    END
  END Tile_X1Y0_N2END[2]
  PIN Tile_X1Y0_N2END[3]
    DIRECTION INPUT ;
    USE SIGNAL ;
    ANTENNAGATEAREA 0.180700 ;
    PORT
      LAYER Metal2 ;
        RECT 303.160 0.000 303.560 0.400 ;
    END
  END Tile_X1Y0_N2END[3]
  PIN Tile_X1Y0_N2END[4]
    DIRECTION INPUT ;
    USE SIGNAL ;
    ANTENNAGATEAREA 0.393900 ;
    PORT
      LAYER Metal2 ;
        RECT 305.080 0.000 305.480 0.400 ;
    END
  END Tile_X1Y0_N2END[4]
  PIN Tile_X1Y0_N2END[5]
    DIRECTION INPUT ;
    USE SIGNAL ;
    ANTENNAGATEAREA 0.393900 ;
    PORT
      LAYER Metal2 ;
        RECT 307.000 0.000 307.400 0.400 ;
    END
  END Tile_X1Y0_N2END[5]
  PIN Tile_X1Y0_N2END[6]
    DIRECTION INPUT ;
    USE SIGNAL ;
    ANTENNAGATEAREA 0.393900 ;
    PORT
      LAYER Metal2 ;
        RECT 308.920 0.000 309.320 0.400 ;
    END
  END Tile_X1Y0_N2END[6]
  PIN Tile_X1Y0_N2END[7]
    DIRECTION INPUT ;
    USE SIGNAL ;
    ANTENNAGATEAREA 0.393900 ;
    PORT
      LAYER Metal2 ;
        RECT 310.840 0.000 311.240 0.400 ;
    END
  END Tile_X1Y0_N2END[7]
  PIN Tile_X1Y0_N2MID[0]
    DIRECTION INPUT ;
    USE SIGNAL ;
    ANTENNAGATEAREA 0.393900 ;
    PORT
      LAYER Metal2 ;
        RECT 281.080 0.000 281.480 0.400 ;
    END
  END Tile_X1Y0_N2MID[0]
  PIN Tile_X1Y0_N2MID[1]
    DIRECTION INPUT ;
    USE SIGNAL ;
    ANTENNAGATEAREA 0.393900 ;
    PORT
      LAYER Metal2 ;
        RECT 283.000 0.000 283.400 0.400 ;
    END
  END Tile_X1Y0_N2MID[1]
  PIN Tile_X1Y0_N2MID[2]
    DIRECTION INPUT ;
    USE SIGNAL ;
    ANTENNAGATEAREA 0.393900 ;
    PORT
      LAYER Metal2 ;
        RECT 284.920 0.000 285.320 0.400 ;
    END
  END Tile_X1Y0_N2MID[2]
  PIN Tile_X1Y0_N2MID[3]
    DIRECTION INPUT ;
    USE SIGNAL ;
    ANTENNAGATEAREA 0.393900 ;
    PORT
      LAYER Metal2 ;
        RECT 286.840 0.000 287.240 0.400 ;
    END
  END Tile_X1Y0_N2MID[3]
  PIN Tile_X1Y0_N2MID[4]
    DIRECTION INPUT ;
    USE SIGNAL ;
    ANTENNAGATEAREA 0.393900 ;
    PORT
      LAYER Metal2 ;
        RECT 288.760 0.000 289.160 0.400 ;
    END
  END Tile_X1Y0_N2MID[4]
  PIN Tile_X1Y0_N2MID[5]
    DIRECTION INPUT ;
    USE SIGNAL ;
    ANTENNAGATEAREA 0.393900 ;
    PORT
      LAYER Metal2 ;
        RECT 290.680 0.000 291.080 0.400 ;
    END
  END Tile_X1Y0_N2MID[5]
  PIN Tile_X1Y0_N2MID[6]
    DIRECTION INPUT ;
    USE SIGNAL ;
    ANTENNAGATEAREA 0.393900 ;
    PORT
      LAYER Metal2 ;
        RECT 292.600 0.000 293.000 0.400 ;
    END
  END Tile_X1Y0_N2MID[6]
  PIN Tile_X1Y0_N2MID[7]
    DIRECTION INPUT ;
    USE SIGNAL ;
    ANTENNAGATEAREA 0.393900 ;
    PORT
      LAYER Metal2 ;
        RECT 294.520 0.000 294.920 0.400 ;
    END
  END Tile_X1Y0_N2MID[7]
  PIN Tile_X1Y0_N4END[0]
    DIRECTION INPUT ;
    USE SIGNAL ;
    ANTENNAGATEAREA 0.607100 ;
    PORT
      LAYER Metal2 ;
        RECT 315.640 0.000 316.040 0.400 ;
    END
  END Tile_X1Y0_N4END[0]
  PIN Tile_X1Y0_N4END[10]
    DIRECTION INPUT ;
    USE SIGNAL ;
    ANTENNAGATEAREA 0.607100 ;
    PORT
      LAYER Metal2 ;
        RECT 334.840 0.000 335.240 0.400 ;
    END
  END Tile_X1Y0_N4END[10]
  PIN Tile_X1Y0_N4END[11]
    DIRECTION INPUT ;
    USE SIGNAL ;
    ANTENNAGATEAREA 0.607100 ;
    PORT
      LAYER Metal2 ;
        RECT 336.760 0.000 337.160 0.400 ;
    END
  END Tile_X1Y0_N4END[11]
  PIN Tile_X1Y0_N4END[12]
    DIRECTION INPUT ;
    USE SIGNAL ;
    ANTENNAGATEAREA 0.393900 ;
    PORT
      LAYER Metal2 ;
        RECT 338.680 0.000 339.080 0.400 ;
    END
  END Tile_X1Y0_N4END[12]
  PIN Tile_X1Y0_N4END[13]
    DIRECTION INPUT ;
    USE SIGNAL ;
    ANTENNAGATEAREA 0.607100 ;
    PORT
      LAYER Metal2 ;
        RECT 340.600 0.000 341.000 0.400 ;
    END
  END Tile_X1Y0_N4END[13]
  PIN Tile_X1Y0_N4END[14]
    DIRECTION INPUT ;
    USE SIGNAL ;
    ANTENNAGATEAREA 0.607100 ;
    PORT
      LAYER Metal2 ;
        RECT 342.520 0.000 342.920 0.400 ;
    END
  END Tile_X1Y0_N4END[14]
  PIN Tile_X1Y0_N4END[15]
    DIRECTION INPUT ;
    USE SIGNAL ;
    ANTENNAGATEAREA 0.393900 ;
    PORT
      LAYER Metal2 ;
        RECT 344.440 0.000 344.840 0.400 ;
    END
  END Tile_X1Y0_N4END[15]
  PIN Tile_X1Y0_N4END[1]
    DIRECTION INPUT ;
    USE SIGNAL ;
    ANTENNAGATEAREA 0.607100 ;
    PORT
      LAYER Metal2 ;
        RECT 317.560 0.000 317.960 0.400 ;
    END
  END Tile_X1Y0_N4END[1]
  PIN Tile_X1Y0_N4END[2]
    DIRECTION INPUT ;
    USE SIGNAL ;
    ANTENNAGATEAREA 0.607100 ;
    PORT
      LAYER Metal2 ;
        RECT 319.480 0.000 319.880 0.400 ;
    END
  END Tile_X1Y0_N4END[2]
  PIN Tile_X1Y0_N4END[3]
    DIRECTION INPUT ;
    USE SIGNAL ;
    ANTENNAGATEAREA 0.607100 ;
    PORT
      LAYER Metal2 ;
        RECT 321.400 0.000 321.800 0.400 ;
    END
  END Tile_X1Y0_N4END[3]
  PIN Tile_X1Y0_N4END[4]
    DIRECTION INPUT ;
    USE SIGNAL ;
    ANTENNAGATEAREA 0.607100 ;
    PORT
      LAYER Metal2 ;
        RECT 323.320 0.000 323.720 0.400 ;
    END
  END Tile_X1Y0_N4END[4]
  PIN Tile_X1Y0_N4END[5]
    DIRECTION INPUT ;
    USE SIGNAL ;
    ANTENNAGATEAREA 0.607100 ;
    PORT
      LAYER Metal2 ;
        RECT 325.240 0.000 325.640 0.400 ;
    END
  END Tile_X1Y0_N4END[5]
  PIN Tile_X1Y0_N4END[6]
    DIRECTION INPUT ;
    USE SIGNAL ;
    ANTENNAGATEAREA 0.607100 ;
    PORT
      LAYER Metal2 ;
        RECT 327.160 0.000 327.560 0.400 ;
    END
  END Tile_X1Y0_N4END[6]
  PIN Tile_X1Y0_N4END[7]
    DIRECTION INPUT ;
    USE SIGNAL ;
    ANTENNAGATEAREA 0.607100 ;
    PORT
      LAYER Metal2 ;
        RECT 329.080 0.000 329.480 0.400 ;
    END
  END Tile_X1Y0_N4END[7]
  PIN Tile_X1Y0_N4END[8]
    DIRECTION INPUT ;
    USE SIGNAL ;
    ANTENNAGATEAREA 0.607100 ;
    PORT
      LAYER Metal2 ;
        RECT 331.000 0.000 331.400 0.400 ;
    END
  END Tile_X1Y0_N4END[8]
  PIN Tile_X1Y0_N4END[9]
    DIRECTION INPUT ;
    USE SIGNAL ;
    ANTENNAGATEAREA 0.607100 ;
    PORT
      LAYER Metal2 ;
        RECT 332.920 0.000 333.320 0.400 ;
    END
  END Tile_X1Y0_N4END[9]
  PIN Tile_X1Y0_NN4END[0]
    DIRECTION INPUT ;
    USE SIGNAL ;
    ANTENNAGATEAREA 0.607100 ;
    PORT
      LAYER Metal2 ;
        RECT 350.200 0.000 350.600 0.400 ;
    END
  END Tile_X1Y0_NN4END[0]
  PIN Tile_X1Y0_NN4END[10]
    DIRECTION INPUT ;
    USE SIGNAL ;
    ANTENNAGATEAREA 0.607100 ;
    PORT
      LAYER Metal2 ;
        RECT 369.400 0.000 369.800 0.400 ;
    END
  END Tile_X1Y0_NN4END[10]
  PIN Tile_X1Y0_NN4END[11]
    DIRECTION INPUT ;
    USE SIGNAL ;
    ANTENNAGATEAREA 0.607100 ;
    PORT
      LAYER Metal2 ;
        RECT 371.320 0.000 371.720 0.400 ;
    END
  END Tile_X1Y0_NN4END[11]
  PIN Tile_X1Y0_NN4END[12]
    DIRECTION INPUT ;
    USE SIGNAL ;
    ANTENNAGATEAREA 0.607100 ;
    PORT
      LAYER Metal2 ;
        RECT 373.240 0.000 373.640 0.400 ;
    END
  END Tile_X1Y0_NN4END[12]
  PIN Tile_X1Y0_NN4END[13]
    DIRECTION INPUT ;
    USE SIGNAL ;
    ANTENNAGATEAREA 0.393900 ;
    PORT
      LAYER Metal2 ;
        RECT 375.160 0.000 375.560 0.400 ;
    END
  END Tile_X1Y0_NN4END[13]
  PIN Tile_X1Y0_NN4END[14]
    DIRECTION INPUT ;
    USE SIGNAL ;
    ANTENNAGATEAREA 0.607100 ;
    PORT
      LAYER Metal2 ;
        RECT 377.080 0.000 377.480 0.400 ;
    END
  END Tile_X1Y0_NN4END[14]
  PIN Tile_X1Y0_NN4END[15]
    DIRECTION INPUT ;
    USE SIGNAL ;
    ANTENNAGATEAREA 0.393900 ;
    PORT
      LAYER Metal2 ;
        RECT 379.000 0.000 379.400 0.400 ;
    END
  END Tile_X1Y0_NN4END[15]
  PIN Tile_X1Y0_NN4END[1]
    DIRECTION INPUT ;
    USE SIGNAL ;
    ANTENNAGATEAREA 0.607100 ;
    PORT
      LAYER Metal2 ;
        RECT 352.120 0.000 352.520 0.400 ;
    END
  END Tile_X1Y0_NN4END[1]
  PIN Tile_X1Y0_NN4END[2]
    DIRECTION INPUT ;
    USE SIGNAL ;
    ANTENNAGATEAREA 0.607100 ;
    PORT
      LAYER Metal2 ;
        RECT 354.040 0.000 354.440 0.400 ;
    END
  END Tile_X1Y0_NN4END[2]
  PIN Tile_X1Y0_NN4END[3]
    DIRECTION INPUT ;
    USE SIGNAL ;
    ANTENNAGATEAREA 0.607100 ;
    PORT
      LAYER Metal2 ;
        RECT 355.960 0.000 356.360 0.400 ;
    END
  END Tile_X1Y0_NN4END[3]
  PIN Tile_X1Y0_NN4END[4]
    DIRECTION INPUT ;
    USE SIGNAL ;
    ANTENNAGATEAREA 0.607100 ;
    PORT
      LAYER Metal2 ;
        RECT 357.880 0.000 358.280 0.400 ;
    END
  END Tile_X1Y0_NN4END[4]
  PIN Tile_X1Y0_NN4END[5]
    DIRECTION INPUT ;
    USE SIGNAL ;
    ANTENNAGATEAREA 0.607100 ;
    PORT
      LAYER Metal2 ;
        RECT 359.800 0.000 360.200 0.400 ;
    END
  END Tile_X1Y0_NN4END[5]
  PIN Tile_X1Y0_NN4END[6]
    DIRECTION INPUT ;
    USE SIGNAL ;
    ANTENNAGATEAREA 0.607100 ;
    PORT
      LAYER Metal2 ;
        RECT 361.720 0.000 362.120 0.400 ;
    END
  END Tile_X1Y0_NN4END[6]
  PIN Tile_X1Y0_NN4END[7]
    DIRECTION INPUT ;
    USE SIGNAL ;
    ANTENNAGATEAREA 0.607100 ;
    PORT
      LAYER Metal2 ;
        RECT 363.640 0.000 364.040 0.400 ;
    END
  END Tile_X1Y0_NN4END[7]
  PIN Tile_X1Y0_NN4END[8]
    DIRECTION INPUT ;
    USE SIGNAL ;
    ANTENNAGATEAREA 0.607100 ;
    PORT
      LAYER Metal2 ;
        RECT 365.560 0.000 365.960 0.400 ;
    END
  END Tile_X1Y0_NN4END[8]
  PIN Tile_X1Y0_NN4END[9]
    DIRECTION INPUT ;
    USE SIGNAL ;
    ANTENNAGATEAREA 0.607100 ;
    PORT
      LAYER Metal2 ;
        RECT 367.480 0.000 367.880 0.400 ;
    END
  END Tile_X1Y0_NN4END[9]
  PIN Tile_X1Y0_S1BEG[0]
    DIRECTION OUTPUT ;
    USE SIGNAL ;
    ANTENNADIFFAREA 2.724000 ;
    PORT
      LAYER Metal2 ;
        RECT 383.800 0.000 384.200 0.400 ;
    END
  END Tile_X1Y0_S1BEG[0]
  PIN Tile_X1Y0_S1BEG[1]
    DIRECTION OUTPUT ;
    USE SIGNAL ;
    ANTENNADIFFAREA 2.724000 ;
    PORT
      LAYER Metal2 ;
        RECT 385.720 0.000 386.120 0.400 ;
    END
  END Tile_X1Y0_S1BEG[1]
  PIN Tile_X1Y0_S1BEG[2]
    DIRECTION OUTPUT ;
    USE SIGNAL ;
    ANTENNADIFFAREA 2.724000 ;
    PORT
      LAYER Metal2 ;
        RECT 387.640 0.000 388.040 0.400 ;
    END
  END Tile_X1Y0_S1BEG[2]
  PIN Tile_X1Y0_S1BEG[3]
    DIRECTION OUTPUT ;
    USE SIGNAL ;
    ANTENNADIFFAREA 2.724000 ;
    PORT
      LAYER Metal2 ;
        RECT 389.560 0.000 389.960 0.400 ;
    END
  END Tile_X1Y0_S1BEG[3]
  PIN Tile_X1Y0_S2BEG[0]
    DIRECTION OUTPUT ;
    USE SIGNAL ;
    ANTENNADIFFAREA 2.724000 ;
    PORT
      LAYER Metal2 ;
        RECT 392.440 0.000 392.840 0.400 ;
    END
  END Tile_X1Y0_S2BEG[0]
  PIN Tile_X1Y0_S2BEG[1]
    DIRECTION OUTPUT ;
    USE SIGNAL ;
    ANTENNADIFFAREA 2.724000 ;
    PORT
      LAYER Metal2 ;
        RECT 394.360 0.000 394.760 0.400 ;
    END
  END Tile_X1Y0_S2BEG[1]
  PIN Tile_X1Y0_S2BEG[2]
    DIRECTION OUTPUT ;
    USE SIGNAL ;
    ANTENNADIFFAREA 2.724000 ;
    PORT
      LAYER Metal2 ;
        RECT 396.280 0.000 396.680 0.400 ;
    END
  END Tile_X1Y0_S2BEG[2]
  PIN Tile_X1Y0_S2BEG[3]
    DIRECTION OUTPUT ;
    USE SIGNAL ;
    ANTENNADIFFAREA 2.724000 ;
    PORT
      LAYER Metal2 ;
        RECT 398.200 0.000 398.600 0.400 ;
    END
  END Tile_X1Y0_S2BEG[3]
  PIN Tile_X1Y0_S2BEG[4]
    DIRECTION OUTPUT ;
    USE SIGNAL ;
    ANTENNADIFFAREA 2.724000 ;
    PORT
      LAYER Metal2 ;
        RECT 400.120 0.000 400.520 0.400 ;
    END
  END Tile_X1Y0_S2BEG[4]
  PIN Tile_X1Y0_S2BEG[5]
    DIRECTION OUTPUT ;
    USE SIGNAL ;
    ANTENNADIFFAREA 2.724000 ;
    PORT
      LAYER Metal2 ;
        RECT 402.040 0.000 402.440 0.400 ;
    END
  END Tile_X1Y0_S2BEG[5]
  PIN Tile_X1Y0_S2BEG[6]
    DIRECTION OUTPUT ;
    USE SIGNAL ;
    ANTENNADIFFAREA 2.724000 ;
    PORT
      LAYER Metal2 ;
        RECT 403.960 0.000 404.360 0.400 ;
    END
  END Tile_X1Y0_S2BEG[6]
  PIN Tile_X1Y0_S2BEG[7]
    DIRECTION OUTPUT ;
    USE SIGNAL ;
    ANTENNADIFFAREA 2.724000 ;
    PORT
      LAYER Metal2 ;
        RECT 405.880 0.000 406.280 0.400 ;
    END
  END Tile_X1Y0_S2BEG[7]
  PIN Tile_X1Y0_S2BEGb[0]
    DIRECTION OUTPUT ;
    USE SIGNAL ;
    ANTENNADIFFAREA 2.724000 ;
    PORT
      LAYER Metal2 ;
        RECT 409.720 0.000 410.120 0.400 ;
    END
  END Tile_X1Y0_S2BEGb[0]
  PIN Tile_X1Y0_S2BEGb[1]
    DIRECTION OUTPUT ;
    USE SIGNAL ;
    ANTENNADIFFAREA 2.724000 ;
    PORT
      LAYER Metal2 ;
        RECT 411.640 0.000 412.040 0.400 ;
    END
  END Tile_X1Y0_S2BEGb[1]
  PIN Tile_X1Y0_S2BEGb[2]
    DIRECTION OUTPUT ;
    USE SIGNAL ;
    ANTENNADIFFAREA 2.724000 ;
    PORT
      LAYER Metal2 ;
        RECT 413.560 0.000 413.960 0.400 ;
    END
  END Tile_X1Y0_S2BEGb[2]
  PIN Tile_X1Y0_S2BEGb[3]
    DIRECTION OUTPUT ;
    USE SIGNAL ;
    ANTENNADIFFAREA 2.724000 ;
    PORT
      LAYER Metal2 ;
        RECT 415.480 0.000 415.880 0.400 ;
    END
  END Tile_X1Y0_S2BEGb[3]
  PIN Tile_X1Y0_S2BEGb[4]
    DIRECTION OUTPUT ;
    USE SIGNAL ;
    ANTENNADIFFAREA 2.724000 ;
    PORT
      LAYER Metal2 ;
        RECT 417.400 0.000 417.800 0.400 ;
    END
  END Tile_X1Y0_S2BEGb[4]
  PIN Tile_X1Y0_S2BEGb[5]
    DIRECTION OUTPUT ;
    USE SIGNAL ;
    ANTENNADIFFAREA 2.724000 ;
    PORT
      LAYER Metal2 ;
        RECT 419.320 0.000 419.720 0.400 ;
    END
  END Tile_X1Y0_S2BEGb[5]
  PIN Tile_X1Y0_S2BEGb[6]
    DIRECTION OUTPUT ;
    USE SIGNAL ;
    ANTENNADIFFAREA 2.724000 ;
    PORT
      LAYER Metal2 ;
        RECT 421.240 0.000 421.640 0.400 ;
    END
  END Tile_X1Y0_S2BEGb[6]
  PIN Tile_X1Y0_S2BEGb[7]
    DIRECTION OUTPUT ;
    USE SIGNAL ;
    ANTENNADIFFAREA 2.724000 ;
    PORT
      LAYER Metal2 ;
        RECT 423.160 0.000 423.560 0.400 ;
    END
  END Tile_X1Y0_S2BEGb[7]
  PIN Tile_X1Y0_S4BEG[0]
    DIRECTION OUTPUT ;
    USE SIGNAL ;
    ANTENNADIFFAREA 2.724000 ;
    PORT
      LAYER Metal2 ;
        RECT 427.960 0.000 428.360 0.400 ;
    END
  END Tile_X1Y0_S4BEG[0]
  PIN Tile_X1Y0_S4BEG[10]
    DIRECTION OUTPUT ;
    USE SIGNAL ;
    ANTENNADIFFAREA 2.724000 ;
    PORT
      LAYER Metal2 ;
        RECT 447.160 0.000 447.560 0.400 ;
    END
  END Tile_X1Y0_S4BEG[10]
  PIN Tile_X1Y0_S4BEG[11]
    DIRECTION OUTPUT ;
    USE SIGNAL ;
    ANTENNADIFFAREA 2.724000 ;
    PORT
      LAYER Metal2 ;
        RECT 449.080 0.000 449.480 0.400 ;
    END
  END Tile_X1Y0_S4BEG[11]
  PIN Tile_X1Y0_S4BEG[12]
    DIRECTION OUTPUT ;
    USE SIGNAL ;
    ANTENNADIFFAREA 2.724000 ;
    PORT
      LAYER Metal2 ;
        RECT 451.000 0.000 451.400 0.400 ;
    END
  END Tile_X1Y0_S4BEG[12]
  PIN Tile_X1Y0_S4BEG[13]
    DIRECTION OUTPUT ;
    USE SIGNAL ;
    ANTENNADIFFAREA 2.724000 ;
    PORT
      LAYER Metal2 ;
        RECT 452.920 0.000 453.320 0.400 ;
    END
  END Tile_X1Y0_S4BEG[13]
  PIN Tile_X1Y0_S4BEG[14]
    DIRECTION OUTPUT ;
    USE SIGNAL ;
    ANTENNADIFFAREA 2.724000 ;
    PORT
      LAYER Metal2 ;
        RECT 454.840 0.000 455.240 0.400 ;
    END
  END Tile_X1Y0_S4BEG[14]
  PIN Tile_X1Y0_S4BEG[15]
    DIRECTION OUTPUT ;
    USE SIGNAL ;
    ANTENNADIFFAREA 2.724000 ;
    PORT
      LAYER Metal2 ;
        RECT 456.760 0.000 457.160 0.400 ;
    END
  END Tile_X1Y0_S4BEG[15]
  PIN Tile_X1Y0_S4BEG[1]
    DIRECTION OUTPUT ;
    USE SIGNAL ;
    ANTENNADIFFAREA 2.724000 ;
    PORT
      LAYER Metal2 ;
        RECT 429.880 0.000 430.280 0.400 ;
    END
  END Tile_X1Y0_S4BEG[1]
  PIN Tile_X1Y0_S4BEG[2]
    DIRECTION OUTPUT ;
    USE SIGNAL ;
    ANTENNADIFFAREA 2.724000 ;
    PORT
      LAYER Metal2 ;
        RECT 431.800 0.000 432.200 0.400 ;
    END
  END Tile_X1Y0_S4BEG[2]
  PIN Tile_X1Y0_S4BEG[3]
    DIRECTION OUTPUT ;
    USE SIGNAL ;
    ANTENNADIFFAREA 2.724000 ;
    PORT
      LAYER Metal2 ;
        RECT 433.720 0.000 434.120 0.400 ;
    END
  END Tile_X1Y0_S4BEG[3]
  PIN Tile_X1Y0_S4BEG[4]
    DIRECTION OUTPUT ;
    USE SIGNAL ;
    ANTENNADIFFAREA 2.724000 ;
    PORT
      LAYER Metal2 ;
        RECT 435.640 0.000 436.040 0.400 ;
    END
  END Tile_X1Y0_S4BEG[4]
  PIN Tile_X1Y0_S4BEG[5]
    DIRECTION OUTPUT ;
    USE SIGNAL ;
    ANTENNADIFFAREA 2.724000 ;
    PORT
      LAYER Metal2 ;
        RECT 437.560 0.000 437.960 0.400 ;
    END
  END Tile_X1Y0_S4BEG[5]
  PIN Tile_X1Y0_S4BEG[6]
    DIRECTION OUTPUT ;
    USE SIGNAL ;
    ANTENNADIFFAREA 2.724000 ;
    PORT
      LAYER Metal2 ;
        RECT 439.480 0.000 439.880 0.400 ;
    END
  END Tile_X1Y0_S4BEG[6]
  PIN Tile_X1Y0_S4BEG[7]
    DIRECTION OUTPUT ;
    USE SIGNAL ;
    ANTENNADIFFAREA 2.724000 ;
    PORT
      LAYER Metal2 ;
        RECT 441.400 0.000 441.800 0.400 ;
    END
  END Tile_X1Y0_S4BEG[7]
  PIN Tile_X1Y0_S4BEG[8]
    DIRECTION OUTPUT ;
    USE SIGNAL ;
    ANTENNADIFFAREA 2.724000 ;
    PORT
      LAYER Metal2 ;
        RECT 443.320 0.000 443.720 0.400 ;
    END
  END Tile_X1Y0_S4BEG[8]
  PIN Tile_X1Y0_S4BEG[9]
    DIRECTION OUTPUT ;
    USE SIGNAL ;
    ANTENNADIFFAREA 2.724000 ;
    PORT
      LAYER Metal2 ;
        RECT 445.240 0.000 445.640 0.400 ;
    END
  END Tile_X1Y0_S4BEG[9]
  PIN Tile_X1Y0_SS4BEG[0]
    DIRECTION OUTPUT ;
    USE SIGNAL ;
    ANTENNADIFFAREA 2.724000 ;
    PORT
      LAYER Metal2 ;
        RECT 462.520 0.000 462.920 0.400 ;
    END
  END Tile_X1Y0_SS4BEG[0]
  PIN Tile_X1Y0_SS4BEG[10]
    DIRECTION OUTPUT ;
    USE SIGNAL ;
    ANTENNADIFFAREA 2.724000 ;
    PORT
      LAYER Metal2 ;
        RECT 481.720 0.000 482.120 0.400 ;
    END
  END Tile_X1Y0_SS4BEG[10]
  PIN Tile_X1Y0_SS4BEG[11]
    DIRECTION OUTPUT ;
    USE SIGNAL ;
    ANTENNADIFFAREA 2.724000 ;
    PORT
      LAYER Metal2 ;
        RECT 483.640 0.000 484.040 0.400 ;
    END
  END Tile_X1Y0_SS4BEG[11]
  PIN Tile_X1Y0_SS4BEG[12]
    DIRECTION OUTPUT ;
    USE SIGNAL ;
    ANTENNADIFFAREA 2.724000 ;
    PORT
      LAYER Metal2 ;
        RECT 485.560 0.000 485.960 0.400 ;
    END
  END Tile_X1Y0_SS4BEG[12]
  PIN Tile_X1Y0_SS4BEG[13]
    DIRECTION OUTPUT ;
    USE SIGNAL ;
    ANTENNADIFFAREA 2.724000 ;
    PORT
      LAYER Metal2 ;
        RECT 487.480 0.000 487.880 0.400 ;
    END
  END Tile_X1Y0_SS4BEG[13]
  PIN Tile_X1Y0_SS4BEG[14]
    DIRECTION OUTPUT ;
    USE SIGNAL ;
    ANTENNADIFFAREA 2.724000 ;
    PORT
      LAYER Metal2 ;
        RECT 489.400 0.000 489.800 0.400 ;
    END
  END Tile_X1Y0_SS4BEG[14]
  PIN Tile_X1Y0_SS4BEG[15]
    DIRECTION OUTPUT ;
    USE SIGNAL ;
    ANTENNADIFFAREA 2.724000 ;
    PORT
      LAYER Metal2 ;
        RECT 491.320 0.000 491.720 0.400 ;
    END
  END Tile_X1Y0_SS4BEG[15]
  PIN Tile_X1Y0_SS4BEG[1]
    DIRECTION OUTPUT ;
    USE SIGNAL ;
    ANTENNADIFFAREA 2.724000 ;
    PORT
      LAYER Metal2 ;
        RECT 464.440 0.000 464.840 0.400 ;
    END
  END Tile_X1Y0_SS4BEG[1]
  PIN Tile_X1Y0_SS4BEG[2]
    DIRECTION OUTPUT ;
    USE SIGNAL ;
    ANTENNADIFFAREA 2.724000 ;
    PORT
      LAYER Metal2 ;
        RECT 466.360 0.000 466.760 0.400 ;
    END
  END Tile_X1Y0_SS4BEG[2]
  PIN Tile_X1Y0_SS4BEG[3]
    DIRECTION OUTPUT ;
    USE SIGNAL ;
    ANTENNADIFFAREA 2.724000 ;
    PORT
      LAYER Metal2 ;
        RECT 468.280 0.000 468.680 0.400 ;
    END
  END Tile_X1Y0_SS4BEG[3]
  PIN Tile_X1Y0_SS4BEG[4]
    DIRECTION OUTPUT ;
    USE SIGNAL ;
    ANTENNADIFFAREA 2.724000 ;
    PORT
      LAYER Metal2 ;
        RECT 470.200 0.000 470.600 0.400 ;
    END
  END Tile_X1Y0_SS4BEG[4]
  PIN Tile_X1Y0_SS4BEG[5]
    DIRECTION OUTPUT ;
    USE SIGNAL ;
    ANTENNADIFFAREA 2.724000 ;
    PORT
      LAYER Metal2 ;
        RECT 472.120 0.000 472.520 0.400 ;
    END
  END Tile_X1Y0_SS4BEG[5]
  PIN Tile_X1Y0_SS4BEG[6]
    DIRECTION OUTPUT ;
    USE SIGNAL ;
    ANTENNADIFFAREA 2.724000 ;
    PORT
      LAYER Metal2 ;
        RECT 474.040 0.000 474.440 0.400 ;
    END
  END Tile_X1Y0_SS4BEG[6]
  PIN Tile_X1Y0_SS4BEG[7]
    DIRECTION OUTPUT ;
    USE SIGNAL ;
    ANTENNADIFFAREA 2.724000 ;
    PORT
      LAYER Metal2 ;
        RECT 475.960 0.000 476.360 0.400 ;
    END
  END Tile_X1Y0_SS4BEG[7]
  PIN Tile_X1Y0_SS4BEG[8]
    DIRECTION OUTPUT ;
    USE SIGNAL ;
    ANTENNADIFFAREA 2.724000 ;
    PORT
      LAYER Metal2 ;
        RECT 477.880 0.000 478.280 0.400 ;
    END
  END Tile_X1Y0_SS4BEG[8]
  PIN Tile_X1Y0_SS4BEG[9]
    DIRECTION OUTPUT ;
    USE SIGNAL ;
    ANTENNADIFFAREA 2.724000 ;
    PORT
      LAYER Metal2 ;
        RECT 479.800 0.000 480.200 0.400 ;
    END
  END Tile_X1Y0_SS4BEG[9]
  PIN Tile_X1Y0_UserCLKo
    DIRECTION OUTPUT ;
    USE SIGNAL ;
    ANTENNADIFFAREA 2.724000 ;
    PORT
      LAYER Metal3 ;
        RECT 540.080 1.900 540.480 2.300 ;
    END
  END Tile_X1Y0_UserCLKo
  PIN VGND
    DIRECTION INOUT ;
    USE GROUND ;
    PORT
      LAYER Metal4 ;
        RECT 15.380 0.000 16.380 75.180 ;
    END
    PORT
      LAYER Metal4 ;
        RECT 65.380 0.000 66.380 75.180 ;
    END
    PORT
      LAYER Metal4 ;
        RECT 115.380 0.000 116.380 75.180 ;
    END
    PORT
      LAYER Metal4 ;
        RECT 165.380 0.000 166.380 75.180 ;
    END
    PORT
      LAYER Metal4 ;
        RECT 215.380 0.000 216.380 75.180 ;
    END
    PORT
      LAYER Metal4 ;
        RECT 265.380 0.000 266.380 75.180 ;
    END
    PORT
      LAYER Metal4 ;
        RECT 285.620 0.000 286.620 75.180 ;
    END
    PORT
      LAYER Metal4 ;
        RECT 335.620 0.000 336.620 75.180 ;
    END
    PORT
      LAYER Metal4 ;
        RECT 385.620 0.000 386.620 75.180 ;
    END
    PORT
      LAYER Metal4 ;
        RECT 435.620 0.000 436.620 75.180 ;
    END
    PORT
      LAYER Metal4 ;
        RECT 485.620 0.000 486.620 75.180 ;
    END
    PORT
      LAYER Metal4 ;
        RECT 535.620 0.000 536.620 75.180 ;
    END
  END VGND
  PIN VPWR
    DIRECTION INOUT ;
    USE POWER ;
    PORT
      LAYER Metal4 ;
        RECT 12.380 0.000 13.380 75.180 ;
    END
    PORT
      LAYER Metal4 ;
        RECT 62.380 0.000 63.380 75.180 ;
    END
    PORT
      LAYER Metal4 ;
        RECT 112.380 0.000 113.380 75.180 ;
    END
    PORT
      LAYER Metal4 ;
        RECT 162.380 0.000 163.380 75.180 ;
    END
    PORT
      LAYER Metal4 ;
        RECT 212.380 0.000 213.380 75.180 ;
    END
    PORT
      LAYER Metal4 ;
        RECT 262.380 0.000 263.380 75.180 ;
    END
    PORT
      LAYER Metal4 ;
        RECT 282.620 0.000 283.620 75.180 ;
    END
    PORT
      LAYER Metal4 ;
        RECT 332.620 0.000 333.620 75.180 ;
    END
    PORT
      LAYER Metal4 ;
        RECT 382.620 0.000 383.620 75.180 ;
    END
    PORT
      LAYER Metal4 ;
        RECT 432.620 0.000 433.620 75.180 ;
    END
    PORT
      LAYER Metal4 ;
        RECT 482.620 0.000 483.620 75.180 ;
    END
    PORT
      LAYER Metal4 ;
        RECT 532.620 0.000 533.620 75.180 ;
    END
  END VPWR
  OBS
      LAYER GatPoly ;
        RECT 2.880 3.630 537.600 68.190 ;
      LAYER Metal1 ;
        RECT 2.880 3.560 537.600 68.260 ;
      LAYER Metal2 ;
        RECT 1.815 74.570 7.750 74.905 ;
        RECT 8.570 74.570 21.190 74.905 ;
        RECT 22.010 74.570 34.630 74.905 ;
        RECT 35.450 74.570 48.070 74.905 ;
        RECT 48.890 74.570 61.510 74.905 ;
        RECT 62.330 74.570 74.950 74.905 ;
        RECT 75.770 74.570 88.390 74.905 ;
        RECT 89.210 74.570 101.830 74.905 ;
        RECT 102.650 74.570 115.270 74.905 ;
        RECT 116.090 74.570 128.710 74.905 ;
        RECT 129.530 74.570 142.150 74.905 ;
        RECT 142.970 74.570 155.590 74.905 ;
        RECT 156.410 74.570 169.030 74.905 ;
        RECT 169.850 74.570 182.470 74.905 ;
        RECT 183.290 74.570 195.910 74.905 ;
        RECT 196.730 74.570 209.350 74.905 ;
        RECT 210.170 74.570 222.790 74.905 ;
        RECT 223.610 74.570 236.230 74.905 ;
        RECT 237.050 74.570 249.670 74.905 ;
        RECT 250.490 74.570 263.110 74.905 ;
        RECT 263.930 74.570 280.870 74.905 ;
        RECT 281.690 74.570 284.710 74.905 ;
        RECT 285.530 74.570 288.550 74.905 ;
        RECT 289.370 74.570 292.390 74.905 ;
        RECT 293.210 74.570 296.230 74.905 ;
        RECT 297.050 74.570 300.070 74.905 ;
        RECT 300.890 74.570 303.910 74.905 ;
        RECT 304.730 74.570 307.750 74.905 ;
        RECT 308.570 74.570 311.590 74.905 ;
        RECT 312.410 74.570 315.430 74.905 ;
        RECT 316.250 74.570 319.270 74.905 ;
        RECT 320.090 74.570 323.110 74.905 ;
        RECT 323.930 74.570 326.950 74.905 ;
        RECT 327.770 74.570 330.790 74.905 ;
        RECT 331.610 74.570 334.630 74.905 ;
        RECT 335.450 74.570 338.470 74.905 ;
        RECT 339.290 74.570 342.310 74.905 ;
        RECT 343.130 74.570 346.150 74.905 ;
        RECT 346.970 74.570 349.990 74.905 ;
        RECT 350.810 74.570 353.830 74.905 ;
        RECT 354.650 74.570 383.590 74.905 ;
        RECT 384.410 74.570 387.430 74.905 ;
        RECT 388.250 74.570 391.270 74.905 ;
        RECT 392.090 74.570 395.110 74.905 ;
        RECT 395.930 74.570 398.950 74.905 ;
        RECT 399.770 74.570 402.790 74.905 ;
        RECT 403.610 74.570 406.630 74.905 ;
        RECT 407.450 74.570 410.470 74.905 ;
        RECT 411.290 74.570 414.310 74.905 ;
        RECT 415.130 74.570 418.150 74.905 ;
        RECT 418.970 74.570 421.990 74.905 ;
        RECT 422.810 74.570 425.830 74.905 ;
        RECT 426.650 74.570 429.670 74.905 ;
        RECT 430.490 74.570 433.510 74.905 ;
        RECT 434.330 74.570 437.350 74.905 ;
        RECT 438.170 74.570 441.190 74.905 ;
        RECT 442.010 74.570 445.030 74.905 ;
        RECT 445.850 74.570 448.870 74.905 ;
        RECT 449.690 74.570 452.710 74.905 ;
        RECT 453.530 74.570 456.550 74.905 ;
        RECT 457.370 74.570 460.390 74.905 ;
        RECT 461.210 74.570 464.230 74.905 ;
        RECT 465.050 74.570 468.070 74.905 ;
        RECT 468.890 74.570 471.910 74.905 ;
        RECT 472.730 74.570 475.750 74.905 ;
        RECT 476.570 74.570 479.590 74.905 ;
        RECT 480.410 74.570 483.430 74.905 ;
        RECT 484.250 74.570 487.270 74.905 ;
        RECT 488.090 74.570 491.110 74.905 ;
        RECT 491.930 74.570 494.950 74.905 ;
        RECT 495.770 74.570 498.790 74.905 ;
        RECT 499.610 74.570 502.630 74.905 ;
        RECT 503.450 74.570 506.470 74.905 ;
        RECT 507.290 74.570 510.310 74.905 ;
        RECT 511.130 74.570 514.150 74.905 ;
        RECT 514.970 74.570 517.990 74.905 ;
        RECT 518.810 74.570 521.830 74.905 ;
        RECT 522.650 74.570 537.705 74.905 ;
        RECT 1.815 0.610 537.705 74.570 ;
        RECT 1.815 0.275 1.990 0.610 ;
        RECT 2.810 0.275 3.910 0.610 ;
        RECT 4.730 0.275 5.830 0.610 ;
        RECT 6.650 0.275 7.750 0.610 ;
        RECT 8.570 0.275 10.630 0.610 ;
        RECT 11.450 0.275 12.550 0.610 ;
        RECT 13.370 0.275 14.470 0.610 ;
        RECT 15.290 0.275 16.390 0.610 ;
        RECT 17.210 0.275 18.310 0.610 ;
        RECT 19.130 0.275 20.230 0.610 ;
        RECT 21.050 0.275 22.150 0.610 ;
        RECT 22.970 0.275 24.070 0.610 ;
        RECT 24.890 0.275 26.950 0.610 ;
        RECT 27.770 0.275 28.870 0.610 ;
        RECT 29.690 0.275 30.790 0.610 ;
        RECT 31.610 0.275 32.710 0.610 ;
        RECT 33.530 0.275 34.630 0.610 ;
        RECT 35.450 0.275 36.550 0.610 ;
        RECT 37.370 0.275 38.470 0.610 ;
        RECT 39.290 0.275 40.390 0.610 ;
        RECT 41.210 0.275 45.190 0.610 ;
        RECT 46.010 0.275 47.110 0.610 ;
        RECT 47.930 0.275 49.030 0.610 ;
        RECT 49.850 0.275 50.950 0.610 ;
        RECT 51.770 0.275 52.870 0.610 ;
        RECT 53.690 0.275 54.790 0.610 ;
        RECT 55.610 0.275 56.710 0.610 ;
        RECT 57.530 0.275 58.630 0.610 ;
        RECT 59.450 0.275 60.550 0.610 ;
        RECT 61.370 0.275 62.470 0.610 ;
        RECT 63.290 0.275 64.390 0.610 ;
        RECT 65.210 0.275 66.310 0.610 ;
        RECT 67.130 0.275 68.230 0.610 ;
        RECT 69.050 0.275 70.150 0.610 ;
        RECT 70.970 0.275 72.070 0.610 ;
        RECT 72.890 0.275 73.990 0.610 ;
        RECT 74.810 0.275 79.750 0.610 ;
        RECT 80.570 0.275 81.670 0.610 ;
        RECT 82.490 0.275 83.590 0.610 ;
        RECT 84.410 0.275 85.510 0.610 ;
        RECT 86.330 0.275 87.430 0.610 ;
        RECT 88.250 0.275 89.350 0.610 ;
        RECT 90.170 0.275 91.270 0.610 ;
        RECT 92.090 0.275 93.190 0.610 ;
        RECT 94.010 0.275 95.110 0.610 ;
        RECT 95.930 0.275 97.030 0.610 ;
        RECT 97.850 0.275 98.950 0.610 ;
        RECT 99.770 0.275 100.870 0.610 ;
        RECT 101.690 0.275 102.790 0.610 ;
        RECT 103.610 0.275 104.710 0.610 ;
        RECT 105.530 0.275 106.630 0.610 ;
        RECT 107.450 0.275 108.550 0.610 ;
        RECT 109.370 0.275 113.350 0.610 ;
        RECT 114.170 0.275 115.270 0.610 ;
        RECT 116.090 0.275 117.190 0.610 ;
        RECT 118.010 0.275 119.110 0.610 ;
        RECT 119.930 0.275 121.990 0.610 ;
        RECT 122.810 0.275 123.910 0.610 ;
        RECT 124.730 0.275 125.830 0.610 ;
        RECT 126.650 0.275 127.750 0.610 ;
        RECT 128.570 0.275 129.670 0.610 ;
        RECT 130.490 0.275 131.590 0.610 ;
        RECT 132.410 0.275 133.510 0.610 ;
        RECT 134.330 0.275 135.430 0.610 ;
        RECT 136.250 0.275 139.270 0.610 ;
        RECT 140.090 0.275 141.190 0.610 ;
        RECT 142.010 0.275 143.110 0.610 ;
        RECT 143.930 0.275 145.030 0.610 ;
        RECT 145.850 0.275 146.950 0.610 ;
        RECT 147.770 0.275 148.870 0.610 ;
        RECT 149.690 0.275 150.790 0.610 ;
        RECT 151.610 0.275 152.710 0.610 ;
        RECT 153.530 0.275 157.510 0.610 ;
        RECT 158.330 0.275 159.430 0.610 ;
        RECT 160.250 0.275 161.350 0.610 ;
        RECT 162.170 0.275 163.270 0.610 ;
        RECT 164.090 0.275 165.190 0.610 ;
        RECT 166.010 0.275 167.110 0.610 ;
        RECT 167.930 0.275 169.030 0.610 ;
        RECT 169.850 0.275 170.950 0.610 ;
        RECT 171.770 0.275 172.870 0.610 ;
        RECT 173.690 0.275 174.790 0.610 ;
        RECT 175.610 0.275 176.710 0.610 ;
        RECT 177.530 0.275 178.630 0.610 ;
        RECT 179.450 0.275 180.550 0.610 ;
        RECT 181.370 0.275 182.470 0.610 ;
        RECT 183.290 0.275 184.390 0.610 ;
        RECT 185.210 0.275 186.310 0.610 ;
        RECT 187.130 0.275 192.070 0.610 ;
        RECT 192.890 0.275 193.990 0.610 ;
        RECT 194.810 0.275 195.910 0.610 ;
        RECT 196.730 0.275 197.830 0.610 ;
        RECT 198.650 0.275 199.750 0.610 ;
        RECT 200.570 0.275 201.670 0.610 ;
        RECT 202.490 0.275 203.590 0.610 ;
        RECT 204.410 0.275 205.510 0.610 ;
        RECT 206.330 0.275 207.430 0.610 ;
        RECT 208.250 0.275 209.350 0.610 ;
        RECT 210.170 0.275 211.270 0.610 ;
        RECT 212.090 0.275 213.190 0.610 ;
        RECT 214.010 0.275 215.110 0.610 ;
        RECT 215.930 0.275 217.030 0.610 ;
        RECT 217.850 0.275 218.950 0.610 ;
        RECT 219.770 0.275 220.870 0.610 ;
        RECT 221.690 0.275 225.670 0.610 ;
        RECT 226.490 0.275 230.470 0.610 ;
        RECT 231.290 0.275 232.390 0.610 ;
        RECT 233.210 0.275 234.310 0.610 ;
        RECT 235.130 0.275 236.230 0.610 ;
        RECT 237.050 0.275 238.150 0.610 ;
        RECT 238.970 0.275 240.070 0.610 ;
        RECT 240.890 0.275 241.990 0.610 ;
        RECT 242.810 0.275 243.910 0.610 ;
        RECT 244.730 0.275 245.830 0.610 ;
        RECT 246.650 0.275 247.750 0.610 ;
        RECT 248.570 0.275 249.670 0.610 ;
        RECT 250.490 0.275 251.590 0.610 ;
        RECT 252.410 0.275 253.510 0.610 ;
        RECT 254.330 0.275 255.430 0.610 ;
        RECT 256.250 0.275 257.350 0.610 ;
        RECT 258.170 0.275 259.270 0.610 ;
        RECT 260.090 0.275 261.190 0.610 ;
        RECT 262.010 0.275 263.110 0.610 ;
        RECT 263.930 0.275 265.030 0.610 ;
        RECT 265.850 0.275 266.950 0.610 ;
        RECT 267.770 0.275 272.230 0.610 ;
        RECT 273.050 0.275 274.150 0.610 ;
        RECT 274.970 0.275 276.070 0.610 ;
        RECT 276.890 0.275 277.990 0.610 ;
        RECT 278.810 0.275 280.870 0.610 ;
        RECT 281.690 0.275 282.790 0.610 ;
        RECT 283.610 0.275 284.710 0.610 ;
        RECT 285.530 0.275 286.630 0.610 ;
        RECT 287.450 0.275 288.550 0.610 ;
        RECT 289.370 0.275 290.470 0.610 ;
        RECT 291.290 0.275 292.390 0.610 ;
        RECT 293.210 0.275 294.310 0.610 ;
        RECT 295.130 0.275 297.190 0.610 ;
        RECT 298.010 0.275 299.110 0.610 ;
        RECT 299.930 0.275 301.030 0.610 ;
        RECT 301.850 0.275 302.950 0.610 ;
        RECT 303.770 0.275 304.870 0.610 ;
        RECT 305.690 0.275 306.790 0.610 ;
        RECT 307.610 0.275 308.710 0.610 ;
        RECT 309.530 0.275 310.630 0.610 ;
        RECT 311.450 0.275 315.430 0.610 ;
        RECT 316.250 0.275 317.350 0.610 ;
        RECT 318.170 0.275 319.270 0.610 ;
        RECT 320.090 0.275 321.190 0.610 ;
        RECT 322.010 0.275 323.110 0.610 ;
        RECT 323.930 0.275 325.030 0.610 ;
        RECT 325.850 0.275 326.950 0.610 ;
        RECT 327.770 0.275 328.870 0.610 ;
        RECT 329.690 0.275 330.790 0.610 ;
        RECT 331.610 0.275 332.710 0.610 ;
        RECT 333.530 0.275 334.630 0.610 ;
        RECT 335.450 0.275 336.550 0.610 ;
        RECT 337.370 0.275 338.470 0.610 ;
        RECT 339.290 0.275 340.390 0.610 ;
        RECT 341.210 0.275 342.310 0.610 ;
        RECT 343.130 0.275 344.230 0.610 ;
        RECT 345.050 0.275 349.990 0.610 ;
        RECT 350.810 0.275 351.910 0.610 ;
        RECT 352.730 0.275 353.830 0.610 ;
        RECT 354.650 0.275 355.750 0.610 ;
        RECT 356.570 0.275 357.670 0.610 ;
        RECT 358.490 0.275 359.590 0.610 ;
        RECT 360.410 0.275 361.510 0.610 ;
        RECT 362.330 0.275 363.430 0.610 ;
        RECT 364.250 0.275 365.350 0.610 ;
        RECT 366.170 0.275 367.270 0.610 ;
        RECT 368.090 0.275 369.190 0.610 ;
        RECT 370.010 0.275 371.110 0.610 ;
        RECT 371.930 0.275 373.030 0.610 ;
        RECT 373.850 0.275 374.950 0.610 ;
        RECT 375.770 0.275 376.870 0.610 ;
        RECT 377.690 0.275 378.790 0.610 ;
        RECT 379.610 0.275 383.590 0.610 ;
        RECT 384.410 0.275 385.510 0.610 ;
        RECT 386.330 0.275 387.430 0.610 ;
        RECT 388.250 0.275 389.350 0.610 ;
        RECT 390.170 0.275 392.230 0.610 ;
        RECT 393.050 0.275 394.150 0.610 ;
        RECT 394.970 0.275 396.070 0.610 ;
        RECT 396.890 0.275 397.990 0.610 ;
        RECT 398.810 0.275 399.910 0.610 ;
        RECT 400.730 0.275 401.830 0.610 ;
        RECT 402.650 0.275 403.750 0.610 ;
        RECT 404.570 0.275 405.670 0.610 ;
        RECT 406.490 0.275 409.510 0.610 ;
        RECT 410.330 0.275 411.430 0.610 ;
        RECT 412.250 0.275 413.350 0.610 ;
        RECT 414.170 0.275 415.270 0.610 ;
        RECT 416.090 0.275 417.190 0.610 ;
        RECT 418.010 0.275 419.110 0.610 ;
        RECT 419.930 0.275 421.030 0.610 ;
        RECT 421.850 0.275 422.950 0.610 ;
        RECT 423.770 0.275 427.750 0.610 ;
        RECT 428.570 0.275 429.670 0.610 ;
        RECT 430.490 0.275 431.590 0.610 ;
        RECT 432.410 0.275 433.510 0.610 ;
        RECT 434.330 0.275 435.430 0.610 ;
        RECT 436.250 0.275 437.350 0.610 ;
        RECT 438.170 0.275 439.270 0.610 ;
        RECT 440.090 0.275 441.190 0.610 ;
        RECT 442.010 0.275 443.110 0.610 ;
        RECT 443.930 0.275 445.030 0.610 ;
        RECT 445.850 0.275 446.950 0.610 ;
        RECT 447.770 0.275 448.870 0.610 ;
        RECT 449.690 0.275 450.790 0.610 ;
        RECT 451.610 0.275 452.710 0.610 ;
        RECT 453.530 0.275 454.630 0.610 ;
        RECT 455.450 0.275 456.550 0.610 ;
        RECT 457.370 0.275 462.310 0.610 ;
        RECT 463.130 0.275 464.230 0.610 ;
        RECT 465.050 0.275 466.150 0.610 ;
        RECT 466.970 0.275 468.070 0.610 ;
        RECT 468.890 0.275 469.990 0.610 ;
        RECT 470.810 0.275 471.910 0.610 ;
        RECT 472.730 0.275 473.830 0.610 ;
        RECT 474.650 0.275 475.750 0.610 ;
        RECT 476.570 0.275 477.670 0.610 ;
        RECT 478.490 0.275 479.590 0.610 ;
        RECT 480.410 0.275 481.510 0.610 ;
        RECT 482.330 0.275 483.430 0.610 ;
        RECT 484.250 0.275 485.350 0.610 ;
        RECT 486.170 0.275 487.270 0.610 ;
        RECT 488.090 0.275 489.190 0.610 ;
        RECT 490.010 0.275 491.110 0.610 ;
        RECT 491.930 0.275 495.910 0.610 ;
        RECT 496.730 0.275 500.710 0.610 ;
        RECT 501.530 0.275 502.630 0.610 ;
        RECT 503.450 0.275 504.550 0.610 ;
        RECT 505.370 0.275 506.470 0.610 ;
        RECT 507.290 0.275 508.390 0.610 ;
        RECT 509.210 0.275 510.310 0.610 ;
        RECT 511.130 0.275 512.230 0.610 ;
        RECT 513.050 0.275 514.150 0.610 ;
        RECT 514.970 0.275 516.070 0.610 ;
        RECT 516.890 0.275 517.990 0.610 ;
        RECT 518.810 0.275 519.910 0.610 ;
        RECT 520.730 0.275 521.830 0.610 ;
        RECT 522.650 0.275 523.750 0.610 ;
        RECT 524.570 0.275 525.670 0.610 ;
        RECT 526.490 0.275 527.590 0.610 ;
        RECT 528.410 0.275 529.510 0.610 ;
        RECT 530.330 0.275 531.430 0.610 ;
        RECT 532.250 0.275 533.350 0.610 ;
        RECT 534.170 0.275 535.270 0.610 ;
        RECT 536.090 0.275 537.190 0.610 ;
      LAYER Metal3 ;
        RECT 0.380 65.510 540.100 74.865 ;
        RECT 0.610 64.690 539.870 65.510 ;
        RECT 0.380 63.830 540.100 64.690 ;
        RECT 0.610 63.010 539.870 63.830 ;
        RECT 0.380 62.150 540.100 63.010 ;
        RECT 0.610 61.330 539.870 62.150 ;
        RECT 0.380 60.470 540.100 61.330 ;
        RECT 0.610 59.650 539.870 60.470 ;
        RECT 0.380 58.790 540.100 59.650 ;
        RECT 0.610 57.970 539.870 58.790 ;
        RECT 0.380 57.110 540.100 57.970 ;
        RECT 0.610 56.290 539.870 57.110 ;
        RECT 0.380 55.430 540.100 56.290 ;
        RECT 0.610 54.610 539.870 55.430 ;
        RECT 0.380 53.750 540.100 54.610 ;
        RECT 0.610 52.930 539.870 53.750 ;
        RECT 0.380 52.070 540.100 52.930 ;
        RECT 0.610 51.250 539.870 52.070 ;
        RECT 0.380 50.390 540.100 51.250 ;
        RECT 0.610 49.570 539.870 50.390 ;
        RECT 0.380 48.710 540.100 49.570 ;
        RECT 0.610 47.890 539.870 48.710 ;
        RECT 0.380 47.030 540.100 47.890 ;
        RECT 0.610 46.210 539.870 47.030 ;
        RECT 0.380 45.350 540.100 46.210 ;
        RECT 0.610 44.530 539.870 45.350 ;
        RECT 0.380 43.670 540.100 44.530 ;
        RECT 0.610 42.850 539.870 43.670 ;
        RECT 0.380 41.990 540.100 42.850 ;
        RECT 0.610 41.170 539.870 41.990 ;
        RECT 0.380 40.310 540.100 41.170 ;
        RECT 0.610 39.490 539.870 40.310 ;
        RECT 0.380 38.630 540.100 39.490 ;
        RECT 0.610 37.810 539.870 38.630 ;
        RECT 0.380 36.950 540.100 37.810 ;
        RECT 0.610 36.130 539.870 36.950 ;
        RECT 0.380 35.270 540.100 36.130 ;
        RECT 0.610 34.450 539.870 35.270 ;
        RECT 0.380 33.590 540.100 34.450 ;
        RECT 0.610 32.770 539.870 33.590 ;
        RECT 0.380 31.910 540.100 32.770 ;
        RECT 0.610 31.090 539.870 31.910 ;
        RECT 0.380 30.230 540.100 31.090 ;
        RECT 0.610 29.410 539.870 30.230 ;
        RECT 0.380 28.550 540.100 29.410 ;
        RECT 0.610 27.730 539.870 28.550 ;
        RECT 0.380 26.870 540.100 27.730 ;
        RECT 0.610 26.050 539.870 26.870 ;
        RECT 0.380 25.190 540.100 26.050 ;
        RECT 0.610 24.370 539.870 25.190 ;
        RECT 0.380 23.510 540.100 24.370 ;
        RECT 0.610 22.690 539.870 23.510 ;
        RECT 0.380 21.830 540.100 22.690 ;
        RECT 0.610 21.010 539.870 21.830 ;
        RECT 0.380 20.150 540.100 21.010 ;
        RECT 0.610 19.330 539.870 20.150 ;
        RECT 0.380 18.470 540.100 19.330 ;
        RECT 0.610 17.650 539.870 18.470 ;
        RECT 0.380 16.790 540.100 17.650 ;
        RECT 0.610 15.970 539.870 16.790 ;
        RECT 0.380 15.110 540.100 15.970 ;
        RECT 0.610 14.290 539.870 15.110 ;
        RECT 0.380 13.430 540.100 14.290 ;
        RECT 0.610 12.610 539.870 13.430 ;
        RECT 0.380 2.510 540.100 12.610 ;
        RECT 0.610 1.690 539.870 2.510 ;
        RECT 0.380 0.315 540.100 1.690 ;
      LAYER Metal4 ;
        RECT 63.740 0.275 65.170 74.905 ;
        RECT 66.590 0.275 112.170 74.905 ;
        RECT 113.590 0.275 115.170 74.905 ;
        RECT 116.590 0.275 162.170 74.905 ;
        RECT 163.590 0.275 165.170 74.905 ;
        RECT 166.590 0.275 212.170 74.905 ;
        RECT 213.590 0.275 215.170 74.905 ;
        RECT 216.590 0.275 262.170 74.905 ;
        RECT 263.590 0.275 265.170 74.905 ;
        RECT 266.590 0.275 282.410 74.905 ;
        RECT 283.830 0.275 285.410 74.905 ;
        RECT 286.830 0.275 332.410 74.905 ;
        RECT 333.830 0.275 335.410 74.905 ;
        RECT 336.830 0.275 382.410 74.905 ;
        RECT 383.830 0.275 385.410 74.905 ;
        RECT 386.830 0.275 432.410 74.905 ;
        RECT 433.830 0.275 435.410 74.905 ;
        RECT 436.830 0.275 482.410 74.905 ;
        RECT 483.830 0.275 485.410 74.905 ;
        RECT 486.830 0.275 525.910 74.905 ;
      LAYER TopMetal1 ;
        RECT 76.940 3.100 526.420 57.180 ;
  END
END NPU_CTRL_CFG
END LIBRARY

